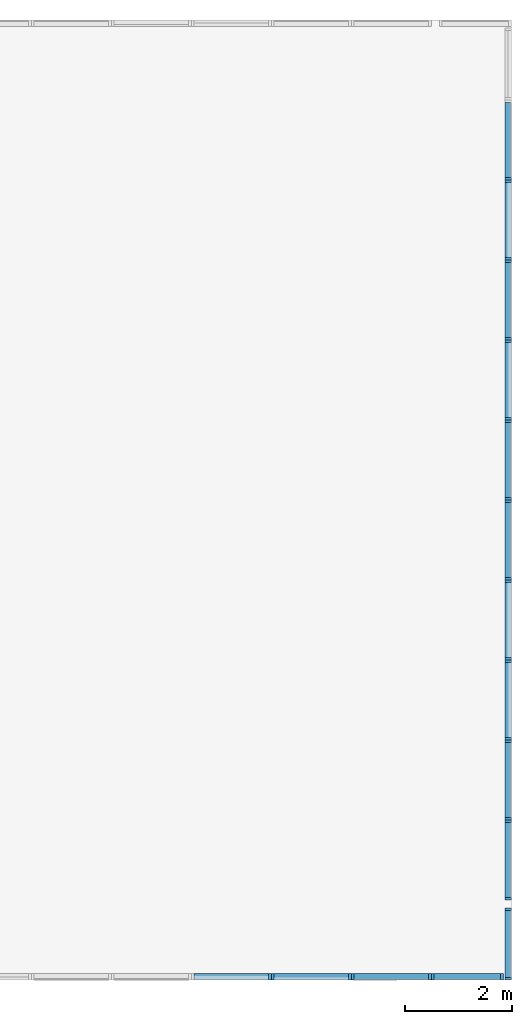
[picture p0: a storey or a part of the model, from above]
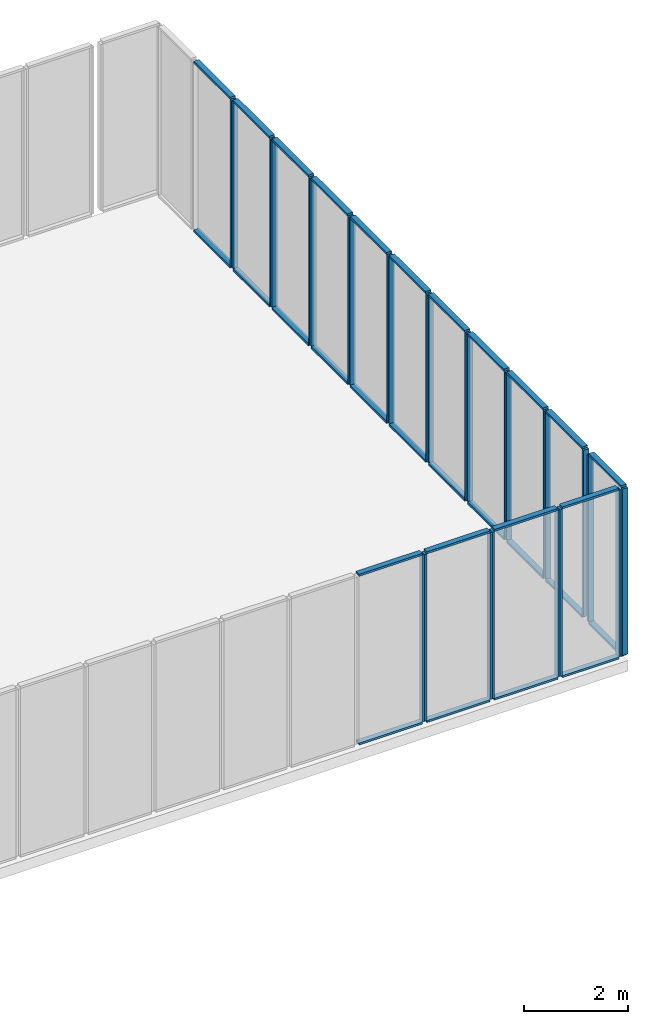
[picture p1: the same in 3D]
Properties of the parts of a building model (IFC4), part 6 of 7

# IfcMember (2304)
Name | In | ElementID | Floor | Elevation | System = Group | Width_mm | Height_mm | Finish | DrawingRef | ParentPanelID
CT-L12-W-007-MR | L12 | CT-L12-W-007-MR | L12 | West | Curtain wall | 50 | 3300 | Blue-grey concept glass | CT-104 | CT-L12-W-007
CT-L12-W-007-FB | L12 | CT-L12-W-007-FB | L12 | West | Curtain wall | 1400 | 50 | Blue-grey concept glass | CT-104 | CT-L12-W-007
CT-L12-W-007-FT | L12 | CT-L12-W-007-FT | L12 | West | Curtain wall | 1400 | 50 | Blue-grey concept glass | CT-104 | CT-L12-W-007
CT-L12-W-008-ML | L12 | CT-L12-W-008-ML | L12 | West | Curtain wall | 50 | 3300 | Blue-grey concept glass | CT-104 | CT-L12-W-008
CT-L12-W-008-MR | L12 | CT-L12-W-008-MR | L12 | West | Curtain wall | 50 | 3300 | Blue-grey concept glass | CT-104 | CT-L12-W-008
CT-L12-W-008-FB | L12 | CT-L12-W-008-FB | L12 | West | Curtain wall | 1250 | 50 | Blue-grey concept glass | CT-104 | CT-L12-W-008
CT-L12-W-008-FT | L12 | CT-L12-W-008-FT | L12 | West | Curtain wall | 1250 | 50 | Blue-grey concept glass | CT-104 | CT-L12-W-008

# IfcMember: Solar shading (57)
PredefinedType: USERDEFINED; Material: Aluminium; Group: Solar shading
ConX_Element - SyntheticData: yes; System: Solar shading; TypeCode: FIN1; Width_mm: 75; Height_mm: 3300; Thickness_mm: 650; Finish: Blue-grey concept glass; DrawingRevision: A
Name | In | ElementID | Floor | Elevation | DrawingRef | ParentPanelID
CT-L04-S-003-FIN | L04 | CT-L04-S-003-FIN | L04 | South | CT-101 | CT-L04-S-003
CT-L04-S-006-FIN | L04 | CT-L04-S-006-FIN | L04 | South | CT-101 | CT-L04-S-006
CT-L04-S-009-FIN | L04 | CT-L04-S-009-FIN | L04 | South | CT-101 | CT-L04-S-009
CT-L04-S-012-FIN | L04 | CT-L04-S-012-FIN | L04 | South | CT-101 | CT-L04-S-012
CT-L04-W-003-FIN | L04 | CT-L04-W-003-FIN | L04 | West | CT-104 | CT-L04-W-003
CT-L04-W-006-FIN | L04 | CT-L04-W-006-FIN | L04 | West | CT-104 | CT-L04-W-006
CT-L04-W-009-FIN | L04 | CT-L04-W-009-FIN | L04 | West | CT-104 | CT-L04-W-009
CT-L05-S-003-FIN | L05 | CT-L05-S-003-FIN | L05 | South | CT-101 | CT-L05-S-003
CT-L05-S-006-FIN | L05 | CT-L05-S-006-FIN | L05 | South | CT-101 | CT-L05-S-006
CT-L05-S-009-FIN | L05 | CT-L05-S-009-FIN | L05 | South | CT-101 | CT-L05-S-009
CT-L05-S-012-FIN | L05 | CT-L05-S-012-FIN | L05 | South | CT-101 | CT-L05-S-012
CT-L05-W-003-FIN | L05 | CT-L05-W-003-FIN | L05 | West | CT-104 | CT-L05-W-003
CT-L05-W-006-FIN | L05 | CT-L05-W-006-FIN | L05 | West | CT-104 | CT-L05-W-006
CT-L05-W-009-FIN | L05 | CT-L05-W-009-FIN | L05 | West | CT-104 | CT-L05-W-009
CT-L06-S-003-FIN | L06 | CT-L06-S-003-FIN | L06 | South | CT-101 | CT-L06-S-003
CT-L06-S-006-FIN | L06 | CT-L06-S-006-FIN | L06 | South | CT-101 | CT-L06-S-006
CT-L06-S-009-FIN | L06 | CT-L06-S-009-FIN | L06 | South | CT-101 | CT-L06-S-009
CT-L06-S-012-FIN | L06 | CT-L06-S-012-FIN | L06 | South | CT-101 | CT-L06-S-012
CT-L06-W-003-FIN | L06 | CT-L06-W-003-FIN | L06 | West | CT-104 | CT-L06-W-003
CT-L06-W-006-FIN | L06 | CT-L06-W-006-FIN | L06 | West | CT-104 | CT-L06-W-006
CT-L06-W-009-FIN | L06 | CT-L06-W-009-FIN | L06 | West | CT-104 | CT-L06-W-009
CT-L07-S-003-FIN | L07 | CT-L07-S-003-FIN | L07 | South | CT-101 | CT-L07-S-003
CT-L07-S-006-FIN | L07 | CT-L07-S-006-FIN | L07 | South | CT-101 | CT-L07-S-006
CT-L07-S-009-FIN | L07 | CT-L07-S-009-FIN | L07 | South | CT-101 | CT-L07-S-009
CT-L07-S-012-FIN | L07 | CT-L07-S-012-FIN | L07 | South | CT-101 | CT-L07-S-012
CT-L07-W-003-FIN | L07 | CT-L07-W-003-FIN | L07 | West | CT-104 | CT-L07-W-003
CT-L07-W-006-FIN | L07 | CT-L07-W-006-FIN | L07 | West | CT-104 | CT-L07-W-006
CT-L07-W-009-FIN | L07 | CT-L07-W-009-FIN | L07 | West | CT-104 | CT-L07-W-009
CT-L08-S-003-FIN | L08 | CT-L08-S-003-FIN | L08 | South | CT-101 | CT-L08-S-003
CT-L08-S-006-FIN | L08 | CT-L08-S-006-FIN | L08 | South | CT-101 | CT-L08-S-006
CT-L08-S-009-FIN | L08 | CT-L08-S-009-FIN | L08 | South | CT-101 | CT-L08-S-009
CT-L08-S-012-FIN | L08 | CT-L08-S-012-FIN | L08 | South | CT-101 | CT-L08-S-012
CT-L08-W-003-FIN | L08 | CT-L08-W-003-FIN | L08 | West | CT-104 | CT-L08-W-003
CT-L08-W-006-FIN | L08 | CT-L08-W-006-FIN | L08 | West | CT-104 | CT-L08-W-006
CT-L08-W-009-FIN | L08 | CT-L08-W-009-FIN | L08 | West | CT-104 | CT-L08-W-009
CT-L09-S-003-FIN | L09 | CT-L09-S-003-FIN | L09 | South | CT-101 | CT-L09-S-003
CT-L09-S-006-FIN | L09 | CT-L09-S-006-FIN | L09 | South | CT-101 | CT-L09-S-006
CT-L09-S-009-FIN | L09 | CT-L09-S-009-FIN | L09 | South | CT-101 | CT-L09-S-009
CT-L09-S-012-FIN | L09 | CT-L09-S-012-FIN | L09 | South | CT-101 | CT-L09-S-012
CT-L09-W-003-FIN | L09 | CT-L09-W-003-FIN | L09 | West | CT-104 | CT-L09-W-003
CT-L09-W-006-FIN | L09 | CT-L09-W-006-FIN | L09 | West | CT-104 | CT-L09-W-006
CT-L09-W-009-FIN | L09 | CT-L09-W-009-FIN | L09 | West | CT-104 | CT-L09-W-009
CT-L10-S-003-FIN | L10 | CT-L10-S-003-FIN | L10 | South | CT-101 | CT-L10-S-003
CT-L10-S-006-FIN | L10 | CT-L10-S-006-FIN | L10 | South | CT-101 | CT-L10-S-006
CT-L10-S-009-FIN | L10 | CT-L10-S-009-FIN | L10 | South | CT-101 | CT-L10-S-009
CT-L10-W-003-FIN | L10 | CT-L10-W-003-FIN | L10 | West | CT-104 | CT-L10-W-003
CT-L10-W-006-FIN | L10 | CT-L10-W-006-FIN | L10 | West | CT-104 | CT-L10-W-006
CT-L11-S-003-FIN | L11 | CT-L11-S-003-FIN | L11 | South | CT-101 | CT-L11-S-003
CT-L11-S-006-FIN | L11 | CT-L11-S-006-FIN | L11 | South | CT-101 | CT-L11-S-006
CT-L11-S-009-FIN | L11 | CT-L11-S-009-FIN | L11 | South | CT-101 | CT-L11-S-009
CT-L11-W-003-FIN | L11 | CT-L11-W-003-FIN | L11 | West | CT-104 | CT-L11-W-003
CT-L11-W-006-FIN | L11 | CT-L11-W-006-FIN | L11 | West | CT-104 | CT-L11-W-006
CT-L12-S-003-FIN | L12 | CT-L12-S-003-FIN | L12 | South | CT-101 | CT-L12-S-003
CT-L12-S-006-FIN | L12 | CT-L12-S-006-FIN | L12 | South | CT-101 | CT-L12-S-006
CT-L12-S-009-FIN | L12 | CT-L12-S-009-FIN | L12 | South | CT-101 | CT-L12-S-009
CT-L12-W-003-FIN | L12 | CT-L12-W-003-FIN | L12 | West | CT-104 | CT-L12-W-003
CT-L12-W-006-FIN | L12 | CT-L12-W-006-FIN | L12 | West | CT-104 | CT-L12-W-006

# IfcPlate (576)
ConX_Element - SyntheticData: yes; DrawingRevision: A
Name | In | PredefinedType | Material | ElementID | Floor | Elevation | System = Group | TypeCode | Width_mm | Height_mm | Thickness_mm | Finish | DrawingRef
CT-L01-S-001 | L01 | CURTAIN_PANEL | Glass | CT-L01-S-001 | L01 | South | Curtain wall | GL1 | 1250 | 3900 | 28 | Blue-grey concept glass | CT-101
CT-L01-S-002 | L01 | CURTAIN_PANEL | Glass | CT-L01-S-002 | L01 | South | Curtain wall | GL1 | 1400 | 3900 | 28 | Blue-grey concept glass | CT-101
CT-L01-S-003 | L01 | CURTAIN_PANEL | Glass | CT-L01-S-003 | L01 | South | Curtain wall | GL1 | 1400 | 3900 | 28 | Blue-grey concept glass | CT-101
CT-L01-S-004 | L01 | SHEET | Stone | CT-L01-S-004 | L01 | South | Stone cladding | ST1 | 1400 | 3900 | 60 | Warm beige stone | CT-101
CT-L01-S-005 | L01 | SHEET | Aluminium | CT-L01-S-005 | L01 | South | Metal rainscreen | AL2 | 1400 | 3900 | 80 | Olive powder coat | CT-101
CT-L01-S-006 | L01 | CURTAIN_PANEL | Glass | CT-L01-S-006 | L01 | South | Curtain wall | GL1 | 1400 | 3900 | 28 | Blue-grey concept glass | CT-101
CT-L01-S-007 | L01 | CURTAIN_PANEL | Glass | CT-L01-S-007 | L01 | South | Curtain wall | GL1 | 1400 | 3900 | 28 | Blue-grey concept glass | CT-101
CT-L01-S-008 | L01 | SHEET | Stone | CT-L01-S-008 | L01 | South | Stone cladding | ST1 | 1400 | 3900 | 60 | Warm beige stone | CT-101
CT-L01-S-009 | L01 | CURTAIN_PANEL | Glass | CT-L01-S-009 | L01 | South | Curtain wall | GL1 | 1400 | 3900 | 28 | Blue-grey concept glass | CT-101
CT-L01-S-010 | L01 | SHEET | Aluminium | CT-L01-S-010 | L01 | South | Metal rainscreen | AL2 | 1400 | 3900 | 80 | Olive powder coat | CT-101
CT-L01-S-011 | L01 | CURTAIN_PANEL | Glass | CT-L01-S-011 | L01 | South | Curtain wall | GL1 | 1400 | 3900 | 28 | Blue-grey concept glass | CT-101
CT-L01-S-012 | L01 | SHEET | Stone | CT-L01-S-012 | L01 | South | Stone cladding | ST1 | 1400 | 3900 | 60 | Warm beige stone | CT-101
CT-L01-S-013 | L01 | CURTAIN_PANEL | Glass | CT-L01-S-013 | L01 | South | Curtain wall | GL1 | 1400 | 3900 | 28 | Blue-grey concept glass | CT-101
CT-L01-S-014 | L01 | CURTAIN_PANEL | Glass | CT-L01-S-014 | L01 | South | Curtain wall | GL1 | 1400 | 3900 | 28 | Blue-grey concept glass | CT-101
CT-L01-S-015 | L01 | SHEET | Aluminium | CT-L01-S-015 | L01 | South | Metal rainscreen | AL2 | 1400 | 3900 | 80 | Olive powder coat | CT-101
CT-L01-S-016 | L01 | SHEET | Stone | CT-L01-S-016 | L01 | South | Stone cladding | ST1 | 1400 | 3900 | 60 | Warm beige stone | CT-101
CT-L01-S-017 | L01 | CURTAIN_PANEL | Glass | CT-L01-S-017 | L01 | South | Curtain wall | GL1 | 1400 | 3900 | 28 | Blue-grey concept glass | CT-101
CT-L01-S-018 | L01 | CURTAIN_PANEL | Glass | CT-L01-S-018 | L01 | South | Curtain wall | GL1 | 1250 | 3900 | 28 | Blue-grey concept glass | CT-101
CT-L01-E-001 | L01 | CURTAIN_PANEL | Glass | CT-L01-E-001 | L01 | East | Curtain wall | GL1 | 1250 | 3900 | 28 | Blue-grey concept glass | CT-102
CT-L01-E-002 | L01 | CURTAIN_PANEL | Glass | CT-L01-E-002 | L01 | East | Curtain wall | GL1 | 1400 | 3900 | 28 | Blue-grey concept glass | CT-102
CT-L01-E-003 | L01 | CURTAIN_PANEL | Glass | CT-L01-E-003 | L01 | East | Curtain wall | GL1 | 1400 | 3900 | 28 | Blue-grey concept glass | CT-102
CT-L01-E-004 | L01 | SHEET | Stone | CT-L01-E-004 | L01 | East | Stone cladding | ST1 | 1400 | 3900 | 60 | Warm beige stone | CT-102
CT-L01-E-005 | L01 | SHEET | Aluminium | CT-L01-E-005 | L01 | East | Metal rainscreen | AL2 | 1400 | 3900 | 80 | Olive powder coat | CT-102
CT-L01-E-006 | L01 | CURTAIN_PANEL | Glass | CT-L01-E-006 | L01 | East | Curtain wall | GL1 | 1400 | 3900 | 28 | Blue-grey concept glass | CT-102
CT-L01-E-007 | L01 | CURTAIN_PANEL | Glass | CT-L01-E-007 | L01 | East | Curtain wall | GL1 | 1400 | 3900 | 28 | Blue-grey concept glass | CT-102
CT-L01-E-008 | L01 | SHEET | Stone | CT-L01-E-008 | L01 | East | Stone cladding | ST1 | 1400 | 3900 | 60 | Warm beige stone | CT-102
CT-L01-E-009 | L01 | CURTAIN_PANEL | Glass | CT-L01-E-009 | L01 | East | Curtain wall | GL1 | 1400 | 3900 | 28 | Blue-grey concept glass | CT-102
CT-L01-E-010 | L01 | SHEET | Aluminium | CT-L01-E-010 | L01 | East | Metal rainscreen | AL2 | 1400 | 3900 | 80 | Olive powder coat | CT-102
CT-L01-E-011 | L01 | CURTAIN_PANEL | Glass | CT-L01-E-011 | L01 | East | Curtain wall | GL1 | 1400 | 3900 | 28 | Blue-grey concept glass | CT-102
CT-L01-E-012 | L01 | SHEET | Stone | CT-L01-E-012 | L01 | East | Stone cladding | ST1 | 1250 | 3900 | 60 | Warm beige stone | CT-102
CT-L01-N-001 | L01 | CURTAIN_PANEL | Glass | CT-L01-N-001 | L01 | North | Curtain wall | GL1 | 1250 | 3900 | 28 | Blue-grey concept glass | CT-103
CT-L01-N-002 | L01 | CURTAIN_PANEL | Glass | CT-L01-N-002 | L01 | North | Curtain wall | GL1 | 1400 | 3900 | 28 | Blue-grey concept glass | CT-103
CT-L01-N-003 | L01 | CURTAIN_PANEL | Glass | CT-L01-N-003 | L01 | North | Curtain wall | GL1 | 1400 | 3900 | 28 | Blue-grey concept glass | CT-103
CT-L01-N-004 | L01 | SHEET | Stone | CT-L01-N-004 | L01 | North | Stone cladding | ST1 | 1400 | 3900 | 60 | Warm beige stone | CT-103
CT-L01-N-005 | L01 | SHEET | Aluminium | CT-L01-N-005 | L01 | North | Metal rainscreen | AL2 | 1400 | 3900 | 80 | Olive powder coat | CT-103
CT-L01-N-006 | L01 | CURTAIN_PANEL | Glass | CT-L01-N-006 | L01 | North | Curtain wall | GL1 | 1400 | 3900 | 28 | Blue-grey concept glass | CT-103
CT-L01-N-007 | L01 | CURTAIN_PANEL | Glass | CT-L01-N-007 | L01 | North | Curtain wall | GL1 | 1400 | 3900 | 28 | Blue-grey concept glass | CT-103
CT-L01-N-008 | L01 | SHEET | Stone | CT-L01-N-008 | L01 | North | Stone cladding | ST1 | 1400 | 3900 | 60 | Warm beige stone | CT-103
CT-L01-N-009 | L01 | CURTAIN_PANEL | Glass | CT-L01-N-009 | L01 | North | Curtain wall | GL1 | 1400 | 3900 | 28 | Blue-grey concept glass | CT-103
CT-L01-N-010 | L01 | SHEET | Aluminium | CT-L01-N-010 | L01 | North | Metal rainscreen | AL2 | 1400 | 3900 | 80 | Olive powder coat | CT-103
CT-L01-N-011 | L01 | CURTAIN_PANEL | Glass | CT-L01-N-011 | L01 | North | Curtain wall | GL1 | 1400 | 3900 | 28 | Blue-grey concept glass | CT-103
CT-L01-N-012 | L01 | SHEET | Stone | CT-L01-N-012 | L01 | North | Stone cladding | ST1 | 1400 | 3900 | 60 | Warm beige stone | CT-103
CT-L01-N-013 | L01 | CURTAIN_PANEL | Glass | CT-L01-N-013 | L01 | North | Curtain wall | GL1 | 1400 | 3900 | 28 | Blue-grey concept glass | CT-103
CT-L01-N-014 | L01 | CURTAIN_PANEL | Glass | CT-L01-N-014 | L01 | North | Curtain wall | GL1 | 1400 | 3900 | 28 | Blue-grey concept glass | CT-103
CT-L01-N-015 | L01 | SHEET | Aluminium | CT-L01-N-015 | L01 | North | Metal rainscreen | AL2 | 1400 | 3900 | 80 | Olive powder coat | CT-103
CT-L01-N-016 | L01 | SHEET | Stone | CT-L01-N-016 | L01 | North | Stone cladding | ST1 | 1400 | 3900 | 60 | Warm beige stone | CT-103
CT-L01-N-017 | L01 | CURTAIN_PANEL | Glass | CT-L01-N-017 | L01 | North | Curtain wall | GL1 | 1400 | 3900 | 28 | Blue-grey concept glass | CT-103
CT-L01-N-018 | L01 | CURTAIN_PANEL | Glass | CT-L01-N-018 | L01 | North | Curtain wall | GL1 | 1250 | 3900 | 28 | Blue-grey concept glass | CT-103
CT-L01-W-001 | L01 | CURTAIN_PANEL | Glass | CT-L01-W-001 | L01 | West | Curtain wall | GL1 | 1250 | 3900 | 28 | Blue-grey concept glass | CT-104
CT-L01-W-002 | L01 | CURTAIN_PANEL | Glass | CT-L01-W-002 | L01 | West | Curtain wall | GL1 | 1400 | 3900 | 28 | Blue-grey concept glass | CT-104
CT-L01-W-003 | L01 | CURTAIN_PANEL | Glass | CT-L01-W-003 | L01 | West | Curtain wall | GL1 | 1400 | 3900 | 28 | Blue-grey concept glass | CT-104
CT-L01-W-004 | L01 | SHEET | Stone | CT-L01-W-004 | L01 | West | Stone cladding | ST1 | 1400 | 3900 | 60 | Warm beige stone | CT-104
CT-L01-W-005 | L01 | SHEET | Aluminium | CT-L01-W-005 | L01 | West | Metal rainscreen | AL2 | 1400 | 3900 | 80 | Olive powder coat | CT-104
CT-L01-W-006 | L01 | CURTAIN_PANEL | Glass | CT-L01-W-006 | L01 | West | Curtain wall | GL1 | 1400 | 3900 | 28 | Blue-grey concept glass | CT-104
CT-L01-W-007 | L01 | CURTAIN_PANEL | Glass | CT-L01-W-007 | L01 | West | Curtain wall | GL1 | 1400 | 3900 | 28 | Blue-grey concept glass | CT-104
CT-L01-W-008 | L01 | SHEET | Stone | CT-L01-W-008 | L01 | West | Stone cladding | ST1 | 1400 | 3900 | 60 | Warm beige stone | CT-104
CT-L01-W-009 | L01 | CURTAIN_PANEL | Glass | CT-L01-W-009 | L01 | West | Curtain wall | GL1 | 1400 | 3900 | 28 | Blue-grey concept glass | CT-104
CT-L01-W-010 | L01 | SHEET | Aluminium | CT-L01-W-010 | L01 | West | Metal rainscreen | AL2 | 1400 | 3900 | 80 | Olive powder coat | CT-104
CT-L01-W-011 | L01 | CURTAIN_PANEL | Glass | CT-L01-W-011 | L01 | West | Curtain wall | GL1 | 1400 | 3900 | 28 | Blue-grey concept glass | CT-104
CT-L01-W-012 | L01 | SHEET | Stone | CT-L01-W-012 | L01 | West | Stone cladding | ST1 | 1250 | 3900 | 60 | Warm beige stone | CT-104
CT-L02-S-001 | L02 | CURTAIN_PANEL | Glass | CT-L02-S-001 | L02 | South | Curtain wall | GL1 | 1250 | 3900 | 28 | Blue-grey concept glass | CT-101
CT-L02-S-002 | L02 | CURTAIN_PANEL | Glass | CT-L02-S-002 | L02 | South | Curtain wall | GL1 | 1400 | 3900 | 28 | Blue-grey concept glass | CT-101
CT-L02-S-003 | L02 | CURTAIN_PANEL | Glass | CT-L02-S-003 | L02 | South | Curtain wall | GL1 | 1400 | 3900 | 28 | Blue-grey concept glass | CT-101
CT-L02-S-004 | L02 | SHEET | Stone | CT-L02-S-004 | L02 | South | Stone cladding | ST1 | 1400 | 3900 | 60 | Warm beige stone | CT-101
CT-L02-S-005 | L02 | SHEET | Aluminium | CT-L02-S-005 | L02 | South | Metal rainscreen | AL2 | 1400 | 3900 | 80 | Olive powder coat | CT-101
CT-L02-S-006 | L02 | CURTAIN_PANEL | Glass | CT-L02-S-006 | L02 | South | Curtain wall | GL1 | 1400 | 3900 | 28 | Blue-grey concept glass | CT-101
CT-L02-S-007 | L02 | CURTAIN_PANEL | Glass | CT-L02-S-007 | L02 | South | Curtain wall | GL1 | 1400 | 3900 | 28 | Blue-grey concept glass | CT-101
CT-L02-S-008 | L02 | SHEET | Stone | CT-L02-S-008 | L02 | South | Stone cladding | ST1 | 1400 | 3900 | 60 | Warm beige stone | CT-101
CT-L02-S-009 | L02 | CURTAIN_PANEL | Glass | CT-L02-S-009 | L02 | South | Curtain wall | GL1 | 1400 | 3900 | 28 | Blue-grey concept glass | CT-101
CT-L02-S-010 | L02 | SHEET | Aluminium | CT-L02-S-010 | L02 | South | Metal rainscreen | AL2 | 1400 | 3900 | 80 | Olive powder coat | CT-101
CT-L02-S-011 | L02 | CURTAIN_PANEL | Glass | CT-L02-S-011 | L02 | South | Curtain wall | GL1 | 1400 | 3900 | 28 | Blue-grey concept glass | CT-101
CT-L02-S-012 | L02 | SHEET | Stone | CT-L02-S-012 | L02 | South | Stone cladding | ST1 | 1400 | 3900 | 60 | Warm beige stone | CT-101
CT-L02-S-013 | L02 | CURTAIN_PANEL | Glass | CT-L02-S-013 | L02 | South | Curtain wall | GL1 | 1400 | 3900 | 28 | Blue-grey concept glass | CT-101
CT-L02-S-014 | L02 | CURTAIN_PANEL | Glass | CT-L02-S-014 | L02 | South | Curtain wall | GL1 | 1400 | 3900 | 28 | Blue-grey concept glass | CT-101
CT-L02-S-015 | L02 | SHEET | Aluminium | CT-L02-S-015 | L02 | South | Metal rainscreen | AL2 | 1400 | 3900 | 80 | Olive powder coat | CT-101
CT-L02-S-016 | L02 | SHEET | Stone | CT-L02-S-016 | L02 | South | Stone cladding | ST1 | 1400 | 3900 | 60 | Warm beige stone | CT-101
CT-L02-S-017 | L02 | CURTAIN_PANEL | Glass | CT-L02-S-017 | L02 | South | Curtain wall | GL1 | 1400 | 3900 | 28 | Blue-grey concept glass | CT-101
CT-L02-S-018 | L02 | CURTAIN_PANEL | Glass | CT-L02-S-018 | L02 | South | Curtain wall | GL1 | 1250 | 3900 | 28 | Blue-grey concept glass | CT-101
CT-L02-E-001 | L02 | CURTAIN_PANEL | Glass | CT-L02-E-001 | L02 | East | Curtain wall | GL1 | 1250 | 3900 | 28 | Blue-grey concept glass | CT-102
CT-L02-E-002 | L02 | CURTAIN_PANEL | Glass | CT-L02-E-002 | L02 | East | Curtain wall | GL1 | 1400 | 3900 | 28 | Blue-grey concept glass | CT-102
CT-L02-E-003 | L02 | CURTAIN_PANEL | Glass | CT-L02-E-003 | L02 | East | Curtain wall | GL1 | 1400 | 3900 | 28 | Blue-grey concept glass | CT-102
CT-L02-E-004 | L02 | SHEET | Stone | CT-L02-E-004 | L02 | East | Stone cladding | ST1 | 1400 | 3900 | 60 | Warm beige stone | CT-102
CT-L02-E-005 | L02 | SHEET | Aluminium | CT-L02-E-005 | L02 | East | Metal rainscreen | AL2 | 1400 | 3900 | 80 | Olive powder coat | CT-102
CT-L02-E-006 | L02 | CURTAIN_PANEL | Glass | CT-L02-E-006 | L02 | East | Curtain wall | GL1 | 1400 | 3900 | 28 | Blue-grey concept glass | CT-102
CT-L02-E-007 | L02 | CURTAIN_PANEL | Glass | CT-L02-E-007 | L02 | East | Curtain wall | GL1 | 1400 | 3900 | 28 | Blue-grey concept glass | CT-102
CT-L02-E-008 | L02 | SHEET | Stone | CT-L02-E-008 | L02 | East | Stone cladding | ST1 | 1400 | 3900 | 60 | Warm beige stone | CT-102
CT-L02-E-009 | L02 | CURTAIN_PANEL | Glass | CT-L02-E-009 | L02 | East | Curtain wall | GL1 | 1400 | 3900 | 28 | Blue-grey concept glass | CT-102
CT-L02-E-010 | L02 | SHEET | Aluminium | CT-L02-E-010 | L02 | East | Metal rainscreen | AL2 | 1400 | 3900 | 80 | Olive powder coat | CT-102
CT-L02-E-011 | L02 | CURTAIN_PANEL | Glass | CT-L02-E-011 | L02 | East | Curtain wall | GL1 | 1400 | 3900 | 28 | Blue-grey concept glass | CT-102
CT-L02-E-012 | L02 | SHEET | Stone | CT-L02-E-012 | L02 | East | Stone cladding | ST1 | 1250 | 3900 | 60 | Warm beige stone | CT-102
CT-L02-N-001 | L02 | CURTAIN_PANEL | Glass | CT-L02-N-001 | L02 | North | Curtain wall | GL1 | 1250 | 3900 | 28 | Blue-grey concept glass | CT-103
CT-L02-N-002 | L02 | CURTAIN_PANEL | Glass | CT-L02-N-002 | L02 | North | Curtain wall | GL1 | 1400 | 3900 | 28 | Blue-grey concept glass | CT-103
CT-L02-N-003 | L02 | CURTAIN_PANEL | Glass | CT-L02-N-003 | L02 | North | Curtain wall | GL1 | 1400 | 3900 | 28 | Blue-grey concept glass | CT-103
CT-L02-N-004 | L02 | SHEET | Stone | CT-L02-N-004 | L02 | North | Stone cladding | ST1 | 1400 | 3900 | 60 | Warm beige stone | CT-103
CT-L02-N-005 | L02 | SHEET | Aluminium | CT-L02-N-005 | L02 | North | Metal rainscreen | AL2 | 1400 | 3900 | 80 | Olive powder coat | CT-103
CT-L02-N-006 | L02 | CURTAIN_PANEL | Glass | CT-L02-N-006 | L02 | North | Curtain wall | GL1 | 1400 | 3900 | 28 | Blue-grey concept glass | CT-103
CT-L02-N-007 | L02 | CURTAIN_PANEL | Glass | CT-L02-N-007 | L02 | North | Curtain wall | GL1 | 1400 | 3900 | 28 | Blue-grey concept glass | CT-103
CT-L02-N-008 | L02 | SHEET | Stone | CT-L02-N-008 | L02 | North | Stone cladding | ST1 | 1400 | 3900 | 60 | Warm beige stone | CT-103
CT-L02-N-009 | L02 | CURTAIN_PANEL | Glass | CT-L02-N-009 | L02 | North | Curtain wall | GL1 | 1400 | 3900 | 28 | Blue-grey concept glass | CT-103
CT-L02-N-010 | L02 | SHEET | Aluminium | CT-L02-N-010 | L02 | North | Metal rainscreen | AL2 | 1400 | 3900 | 80 | Olive powder coat | CT-103
CT-L02-N-011 | L02 | CURTAIN_PANEL | Glass | CT-L02-N-011 | L02 | North | Curtain wall | GL1 | 1400 | 3900 | 28 | Blue-grey concept glass | CT-103
CT-L02-N-012 | L02 | SHEET | Stone | CT-L02-N-012 | L02 | North | Stone cladding | ST1 | 1400 | 3900 | 60 | Warm beige stone | CT-103
CT-L02-N-013 | L02 | CURTAIN_PANEL | Glass | CT-L02-N-013 | L02 | North | Curtain wall | GL1 | 1400 | 3900 | 28 | Blue-grey concept glass | CT-103
CT-L02-N-014 | L02 | CURTAIN_PANEL | Glass | CT-L02-N-014 | L02 | North | Curtain wall | GL1 | 1400 | 3900 | 28 | Blue-grey concept glass | CT-103
CT-L02-N-015 | L02 | SHEET | Aluminium | CT-L02-N-015 | L02 | North | Metal rainscreen | AL2 | 1400 | 3900 | 80 | Olive powder coat | CT-103
CT-L02-N-016 | L02 | SHEET | Stone | CT-L02-N-016 | L02 | North | Stone cladding | ST1 | 1400 | 3900 | 60 | Warm beige stone | CT-103
CT-L02-N-017 | L02 | CURTAIN_PANEL | Glass | CT-L02-N-017 | L02 | North | Curtain wall | GL1 | 1400 | 3900 | 28 | Blue-grey concept glass | CT-103
CT-L02-N-018 | L02 | CURTAIN_PANEL | Glass | CT-L02-N-018 | L02 | North | Curtain wall | GL1 | 1250 | 3900 | 28 | Blue-grey concept glass | CT-103
CT-L02-W-001 | L02 | CURTAIN_PANEL | Glass | CT-L02-W-001 | L02 | West | Curtain wall | GL1 | 1250 | 3900 | 28 | Blue-grey concept glass | CT-104
CT-L02-W-002 | L02 | CURTAIN_PANEL | Glass | CT-L02-W-002 | L02 | West | Curtain wall | GL1 | 1400 | 3900 | 28 | Blue-grey concept glass | CT-104
CT-L02-W-003 | L02 | CURTAIN_PANEL | Glass | CT-L02-W-003 | L02 | West | Curtain wall | GL1 | 1400 | 3900 | 28 | Blue-grey concept glass | CT-104
CT-L02-W-004 | L02 | SHEET | Stone | CT-L02-W-004 | L02 | West | Stone cladding | ST1 | 1400 | 3900 | 60 | Warm beige stone | CT-104
CT-L02-W-005 | L02 | SHEET | Aluminium | CT-L02-W-005 | L02 | West | Metal rainscreen | AL2 | 1400 | 3900 | 80 | Olive powder coat | CT-104
CT-L02-W-006 | L02 | CURTAIN_PANEL | Glass | CT-L02-W-006 | L02 | West | Curtain wall | GL1 | 1400 | 3900 | 28 | Blue-grey concept glass | CT-104
CT-L02-W-007 | L02 | CURTAIN_PANEL | Glass | CT-L02-W-007 | L02 | West | Curtain wall | GL1 | 1400 | 3900 | 28 | Blue-grey concept glass | CT-104
CT-L02-W-008 | L02 | SHEET | Stone | CT-L02-W-008 | L02 | West | Stone cladding | ST1 | 1400 | 3900 | 60 | Warm beige stone | CT-104
CT-L02-W-009 | L02 | CURTAIN_PANEL | Glass | CT-L02-W-009 | L02 | West | Curtain wall | GL1 | 1400 | 3900 | 28 | Blue-grey concept glass | CT-104
CT-L02-W-010 | L02 | SHEET | Aluminium | CT-L02-W-010 | L02 | West | Metal rainscreen | AL2 | 1400 | 3900 | 80 | Olive powder coat | CT-104
CT-L02-W-011 | L02 | CURTAIN_PANEL | Glass | CT-L02-W-011 | L02 | West | Curtain wall | GL1 | 1400 | 3900 | 28 | Blue-grey concept glass | CT-104
CT-L02-W-012 | L02 | SHEET | Stone | CT-L02-W-012 | L02 | West | Stone cladding | ST1 | 1250 | 3900 | 60 | Warm beige stone | CT-104
CT-L03-S-001 | L03 | CURTAIN_PANEL | Glass | CT-L03-S-001 | L03 | South | Curtain wall | GL1 | 1250 | 3900 | 28 | Blue-grey concept glass | CT-101
CT-L03-S-002 | L03 | CURTAIN_PANEL | Glass | CT-L03-S-002 | L03 | South | Curtain wall | GL1 | 1400 | 3900 | 28 | Blue-grey concept glass | CT-101
CT-L03-S-003 | L03 | CURTAIN_PANEL | Glass | CT-L03-S-003 | L03 | South | Curtain wall | GL1 | 1400 | 3900 | 28 | Blue-grey concept glass | CT-101
CT-L03-S-004 | L03 | SHEET | Stone | CT-L03-S-004 | L03 | South | Stone cladding | ST1 | 1400 | 3900 | 60 | Warm beige stone | CT-101
CT-L03-S-005 | L03 | SHEET | Aluminium | CT-L03-S-005 | L03 | South | Metal rainscreen | AL2 | 1400 | 3900 | 80 | Olive powder coat | CT-101
CT-L03-S-006 | L03 | CURTAIN_PANEL | Glass | CT-L03-S-006 | L03 | South | Curtain wall | GL1 | 1400 | 3900 | 28 | Blue-grey concept glass | CT-101
CT-L03-S-007 | L03 | CURTAIN_PANEL | Glass | CT-L03-S-007 | L03 | South | Curtain wall | GL1 | 1400 | 3900 | 28 | Blue-grey concept glass | CT-101
CT-L03-S-008 | L03 | SHEET | Stone | CT-L03-S-008 | L03 | South | Stone cladding | ST1 | 1400 | 3900 | 60 | Warm beige stone | CT-101
CT-L03-S-009 | L03 | CURTAIN_PANEL | Glass | CT-L03-S-009 | L03 | South | Curtain wall | GL1 | 1400 | 3900 | 28 | Blue-grey concept glass | CT-101
CT-L03-S-010 | L03 | SHEET | Aluminium | CT-L03-S-010 | L03 | South | Metal rainscreen | AL2 | 1400 | 3900 | 80 | Olive powder coat | CT-101
CT-L03-S-011 | L03 | CURTAIN_PANEL | Glass | CT-L03-S-011 | L03 | South | Curtain wall | GL1 | 1400 | 3900 | 28 | Blue-grey concept glass | CT-101
CT-L03-S-012 | L03 | SHEET | Stone | CT-L03-S-012 | L03 | South | Stone cladding | ST1 | 1400 | 3900 | 60 | Warm beige stone | CT-101
CT-L03-S-013 | L03 | CURTAIN_PANEL | Glass | CT-L03-S-013 | L03 | South | Curtain wall | GL1 | 1400 | 3900 | 28 | Blue-grey concept glass | CT-101
CT-L03-S-014 | L03 | CURTAIN_PANEL | Glass | CT-L03-S-014 | L03 | South | Curtain wall | GL1 | 1400 | 3900 | 28 | Blue-grey concept glass | CT-101
CT-L03-S-015 | L03 | SHEET | Aluminium | CT-L03-S-015 | L03 | South | Metal rainscreen | AL2 | 1400 | 3900 | 80 | Olive powder coat | CT-101
CT-L03-S-016 | L03 | SHEET | Stone | CT-L03-S-016 | L03 | South | Stone cladding | ST1 | 1400 | 3900 | 60 | Warm beige stone | CT-101
CT-L03-S-017 | L03 | CURTAIN_PANEL | Glass | CT-L03-S-017 | L03 | South | Curtain wall | GL1 | 1400 | 3900 | 28 | Blue-grey concept glass | CT-101
CT-L03-S-018 | L03 | CURTAIN_PANEL | Glass | CT-L03-S-018 | L03 | South | Curtain wall | GL1 | 1250 | 3900 | 28 | Blue-grey concept glass | CT-101
CT-L03-E-001 | L03 | CURTAIN_PANEL | Glass | CT-L03-E-001 | L03 | East | Curtain wall | GL1 | 1250 | 3900 | 28 | Blue-grey concept glass | CT-102
CT-L03-E-002 | L03 | CURTAIN_PANEL | Glass | CT-L03-E-002 | L03 | East | Curtain wall | GL1 | 1400 | 3900 | 28 | Blue-grey concept glass | CT-102
CT-L03-E-003 | L03 | CURTAIN_PANEL | Glass | CT-L03-E-003 | L03 | East | Curtain wall | GL1 | 1400 | 3900 | 28 | Blue-grey concept glass | CT-102
CT-L03-E-004 | L03 | SHEET | Stone | CT-L03-E-004 | L03 | East | Stone cladding | ST1 | 1400 | 3900 | 60 | Warm beige stone | CT-102
CT-L03-E-005 | L03 | SHEET | Aluminium | CT-L03-E-005 | L03 | East | Metal rainscreen | AL2 | 1400 | 3900 | 80 | Olive powder coat | CT-102
CT-L03-E-006 | L03 | CURTAIN_PANEL | Glass | CT-L03-E-006 | L03 | East | Curtain wall | GL1 | 1400 | 3900 | 28 | Blue-grey concept glass | CT-102
CT-L03-E-007 | L03 | CURTAIN_PANEL | Glass | CT-L03-E-007 | L03 | East | Curtain wall | GL1 | 1400 | 3900 | 28 | Blue-grey concept glass | CT-102
CT-L03-E-008 | L03 | SHEET | Stone | CT-L03-E-008 | L03 | East | Stone cladding | ST1 | 1400 | 3900 | 60 | Warm beige stone | CT-102
CT-L03-E-009 | L03 | CURTAIN_PANEL | Glass | CT-L03-E-009 | L03 | East | Curtain wall | GL1 | 1400 | 3900 | 28 | Blue-grey concept glass | CT-102
CT-L03-E-010 | L03 | SHEET | Aluminium | CT-L03-E-010 | L03 | East | Metal rainscreen | AL2 | 1400 | 3900 | 80 | Olive powder coat | CT-102
CT-L03-E-011 | L03 | CURTAIN_PANEL | Glass | CT-L03-E-011 | L03 | East | Curtain wall | GL1 | 1400 | 3900 | 28 | Blue-grey concept glass | CT-102
CT-L03-E-012 | L03 | SHEET | Stone | CT-L03-E-012 | L03 | East | Stone cladding | ST1 | 1250 | 3900 | 60 | Warm beige stone | CT-102
CT-L03-N-001 | L03 | CURTAIN_PANEL | Glass | CT-L03-N-001 | L03 | North | Curtain wall | GL1 | 1250 | 3900 | 28 | Blue-grey concept glass | CT-103
CT-L03-N-002 | L03 | CURTAIN_PANEL | Glass | CT-L03-N-002 | L03 | North | Curtain wall | GL1 | 1400 | 3900 | 28 | Blue-grey concept glass | CT-103
CT-L03-N-003 | L03 | CURTAIN_PANEL | Glass | CT-L03-N-003 | L03 | North | Curtain wall | GL1 | 1400 | 3900 | 28 | Blue-grey concept glass | CT-103
CT-L03-N-004 | L03 | SHEET | Stone | CT-L03-N-004 | L03 | North | Stone cladding | ST1 | 1400 | 3900 | 60 | Warm beige stone | CT-103
CT-L03-N-005 | L03 | SHEET | Aluminium | CT-L03-N-005 | L03 | North | Metal rainscreen | AL2 | 1400 | 3900 | 80 | Olive powder coat | CT-103
CT-L03-N-006 | L03 | CURTAIN_PANEL | Glass | CT-L03-N-006 | L03 | North | Curtain wall | GL1 | 1400 | 3900 | 28 | Blue-grey concept glass | CT-103
CT-L03-N-007 | L03 | CURTAIN_PANEL | Glass | CT-L03-N-007 | L03 | North | Curtain wall | GL1 | 1400 | 3900 | 28 | Blue-grey concept glass | CT-103
CT-L03-N-008 | L03 | SHEET | Stone | CT-L03-N-008 | L03 | North | Stone cladding | ST1 | 1400 | 3900 | 60 | Warm beige stone | CT-103
CT-L03-N-009 | L03 | CURTAIN_PANEL | Glass | CT-L03-N-009 | L03 | North | Curtain wall | GL1 | 1400 | 3900 | 28 | Blue-grey concept glass | CT-103
CT-L03-N-010 | L03 | SHEET | Aluminium | CT-L03-N-010 | L03 | North | Metal rainscreen | AL2 | 1400 | 3900 | 80 | Olive powder coat | CT-103
CT-L03-N-011 | L03 | CURTAIN_PANEL | Glass | CT-L03-N-011 | L03 | North | Curtain wall | GL1 | 1400 | 3900 | 28 | Blue-grey concept glass | CT-103
CT-L03-N-012 | L03 | SHEET | Stone | CT-L03-N-012 | L03 | North | Stone cladding | ST1 | 1400 | 3900 | 60 | Warm beige stone | CT-103
CT-L03-N-013 | L03 | CURTAIN_PANEL | Glass | CT-L03-N-013 | L03 | North | Curtain wall | GL1 | 1400 | 3900 | 28 | Blue-grey concept glass | CT-103
CT-L03-N-014 | L03 | CURTAIN_PANEL | Glass | CT-L03-N-014 | L03 | North | Curtain wall | GL1 | 1400 | 3900 | 28 | Blue-grey concept glass | CT-103
CT-L03-N-015 | L03 | SHEET | Aluminium | CT-L03-N-015 | L03 | North | Metal rainscreen | AL2 | 1400 | 3900 | 80 | Olive powder coat | CT-103
CT-L03-N-016 | L03 | SHEET | Stone | CT-L03-N-016 | L03 | North | Stone cladding | ST1 | 1400 | 3900 | 60 | Warm beige stone | CT-103
CT-L03-N-017 | L03 | CURTAIN_PANEL | Glass | CT-L03-N-017 | L03 | North | Curtain wall | GL1 | 1400 | 3900 | 28 | Blue-grey concept glass | CT-103
CT-L03-N-018 | L03 | CURTAIN_PANEL | Glass | CT-L03-N-018 | L03 | North | Curtain wall | GL1 | 1250 | 3900 | 28 | Blue-grey concept glass | CT-103
CT-L03-W-001 | L03 | CURTAIN_PANEL | Glass | CT-L03-W-001 | L03 | West | Curtain wall | GL1 | 1250 | 3900 | 28 | Blue-grey concept glass | CT-104
CT-L03-W-002 | L03 | CURTAIN_PANEL | Glass | CT-L03-W-002 | L03 | West | Curtain wall | GL1 | 1400 | 3900 | 28 | Blue-grey concept glass | CT-104
CT-L03-W-003 | L03 | CURTAIN_PANEL | Glass | CT-L03-W-003 | L03 | West | Curtain wall | GL1 | 1400 | 3900 | 28 | Blue-grey concept glass | CT-104
CT-L03-W-004 | L03 | SHEET | Stone | CT-L03-W-004 | L03 | West | Stone cladding | ST1 | 1400 | 3900 | 60 | Warm beige stone | CT-104
CT-L03-W-005 | L03 | SHEET | Aluminium | CT-L03-W-005 | L03 | West | Metal rainscreen | AL2 | 1400 | 3900 | 80 | Olive powder coat | CT-104
CT-L03-W-006 | L03 | CURTAIN_PANEL | Glass | CT-L03-W-006 | L03 | West | Curtain wall | GL1 | 1400 | 3900 | 28 | Blue-grey concept glass | CT-104
CT-L03-W-007 | L03 | CURTAIN_PANEL | Glass | CT-L03-W-007 | L03 | West | Curtain wall | GL1 | 1400 | 3900 | 28 | Blue-grey concept glass | CT-104
CT-L03-W-008 | L03 | SHEET | Stone | CT-L03-W-008 | L03 | West | Stone cladding | ST1 | 1400 | 3900 | 60 | Warm beige stone | CT-104
CT-L03-W-009 | L03 | CURTAIN_PANEL | Glass | CT-L03-W-009 | L03 | West | Curtain wall | GL1 | 1400 | 3900 | 28 | Blue-grey concept glass | CT-104
CT-L03-W-010 | L03 | SHEET | Aluminium | CT-L03-W-010 | L03 | West | Metal rainscreen | AL2 | 1400 | 3900 | 80 | Olive powder coat | CT-104
CT-L03-W-011 | L03 | CURTAIN_PANEL | Glass | CT-L03-W-011 | L03 | West | Curtain wall | GL1 | 1400 | 3900 | 28 | Blue-grey concept glass | CT-104
CT-L03-W-012 | L03 | SHEET | Stone | CT-L03-W-012 | L03 | West | Stone cladding | ST1 | 1250 | 3900 | 60 | Warm beige stone | CT-104
CT-L04-S-001 | L04 | CURTAIN_PANEL | Glass | CT-L04-S-001 | L04 | South | Curtain wall | GL1 | 1250 | 3300 | 28 | Blue-grey concept glass | CT-101
CT-L04-S-002 | L04 | CURTAIN_PANEL | Glass | CT-L04-S-002 | L04 | South | Curtain wall | GL1 | 1400 | 3300 | 28 | Blue-grey concept glass | CT-101
CT-L04-S-003 | L04 | CURTAIN_PANEL | Glass | CT-L04-S-003 | L04 | South | Curtain wall | GL1 | 1400 | 3300 | 28 | Blue-grey concept glass | CT-101
CT-L04-S-004 | L04 | CURTAIN_PANEL | Glass | CT-L04-S-004 | L04 | South | Curtain wall | GL1 | 1400 | 3300 | 28 | Blue-grey concept glass | CT-101
CT-L04-S-005 | L04 | SHEET | Aluminium | CT-L04-S-005 | L04 | South | Metal rainscreen | AL2 | 1400 | 3300 | 80 | Olive powder coat | CT-101
CT-L04-S-006 | L04 | CURTAIN_PANEL | Glass | CT-L04-S-006 | L04 | South | Curtain wall | GL1 | 1400 | 3300 | 28 | Blue-grey concept glass | CT-101
CT-L04-S-007 | L04 | CURTAIN_PANEL | Glass | CT-L04-S-007 | L04 | South | Curtain wall | GL1 | 1400 | 3300 | 28 | Blue-grey concept glass | CT-101
CT-L04-S-008 | L04 | CURTAIN_PANEL | Glass | CT-L04-S-008 | L04 | South | Curtain wall | GL1 | 1400 | 3300 | 28 | Blue-grey concept glass | CT-101
CT-L04-S-009 | L04 | CURTAIN_PANEL | Glass | CT-L04-S-009 | L04 | South | Curtain wall | GL1 | 1400 | 3300 | 28 | Blue-grey concept glass | CT-101
CT-L04-S-010 | L04 | SHEET | Aluminium | CT-L04-S-010 | L04 | South | Metal rainscreen | AL2 | 1400 | 3300 | 80 | Olive powder coat | CT-101
CT-L04-S-011 | L04 | CURTAIN_PANEL | Glass | CT-L04-S-011 | L04 | South | Curtain wall | GL1 | 1400 | 3300 | 28 | Blue-grey concept glass | CT-101
CT-L04-S-012 | L04 | CURTAIN_PANEL | Glass | CT-L04-S-012 | L04 | South | Curtain wall | GL1 | 1400 | 3300 | 28 | Blue-grey concept glass | CT-101
CT-L04-S-013 | L04 | CURTAIN_PANEL | Glass | CT-L04-S-013 | L04 | South | Curtain wall | GL1 | 1400 | 3300 | 28 | Blue-grey concept glass | CT-101
CT-L04-S-014 | L04 | CURTAIN_PANEL | Glass | CT-L04-S-014 | L04 | South | Curtain wall | GL1 | 1250 | 3300 | 28 | Blue-grey concept glass | CT-101
CT-L04-E-001 | L04 | CURTAIN_PANEL | Glass | CT-L04-E-001 | L04 | East | Curtain wall | GL1 | 1250 | 3300 | 28 | Blue-grey concept glass | CT-102
CT-L04-E-002 | L04 | CURTAIN_PANEL | Glass | CT-L04-E-002 | L04 | East | Curtain wall | GL1 | 1400 | 3300 | 28 | Blue-grey concept glass | CT-102
CT-L04-E-003 | L04 | CURTAIN_PANEL | Glass | CT-L04-E-003 | L04 | East | Curtain wall | GL1 | 1400 | 3300 | 28 | Blue-grey concept glass | CT-102
CT-L04-E-004 | L04 | CURTAIN_PANEL | Glass | CT-L04-E-004 | L04 | East | Curtain wall | GL1 | 1400 | 3300 | 28 | Blue-grey concept glass | CT-102
CT-L04-E-005 | L04 | SHEET | Aluminium | CT-L04-E-005 | L04 | East | Metal rainscreen | AL2 | 1400 | 3300 | 80 | Olive powder coat | CT-102
CT-L04-E-006 | L04 | CURTAIN_PANEL | Glass | CT-L04-E-006 | L04 | East | Curtain wall | GL1 | 1400 | 3300 | 28 | Blue-grey concept glass | CT-102
CT-L04-E-007 | L04 | CURTAIN_PANEL | Glass | CT-L04-E-007 | L04 | East | Curtain wall | GL1 | 1400 | 3300 | 28 | Blue-grey concept glass | CT-102
CT-L04-E-008 | L04 | CURTAIN_PANEL | Glass | CT-L04-E-008 | L04 | East | Curtain wall | GL1 | 1400 | 3300 | 28 | Blue-grey concept glass | CT-102
CT-L04-E-009 | L04 | CURTAIN_PANEL | Glass | CT-L04-E-009 | L04 | East | Curtain wall | GL1 | 1400 | 3300 | 28 | Blue-grey concept glass | CT-102
CT-L04-E-010 | L04 | SHEET | Aluminium | CT-L04-E-010 | L04 | East | Metal rainscreen | AL2 | 1250 | 3300 | 80 | Olive powder coat | CT-102
CT-L04-N-001 | L04 | CURTAIN_PANEL | Glass | CT-L04-N-001 | L04 | North | Curtain wall | GL1 | 1250 | 3300 | 28 | Blue-grey concept glass | CT-103
CT-L04-N-002 | L04 | CURTAIN_PANEL | Glass | CT-L04-N-002 | L04 | North | Curtain wall | GL1 | 1400 | 3300 | 28 | Blue-grey concept glass | CT-103
CT-L04-N-003 | L04 | CURTAIN_PANEL | Glass | CT-L04-N-003 | L04 | North | Curtain wall | GL1 | 1400 | 3300 | 28 | Blue-grey concept glass | CT-103
CT-L04-N-004 | L04 | CURTAIN_PANEL | Glass | CT-L04-N-004 | L04 | North | Curtain wall | GL1 | 1400 | 3300 | 28 | Blue-grey concept glass | CT-103
CT-L04-N-005 | L04 | SHEET | Aluminium | CT-L04-N-005 | L04 | North | Metal rainscreen | AL2 | 1400 | 3300 | 80 | Olive powder coat | CT-103
CT-L04-N-006 | L04 | CURTAIN_PANEL | Glass | CT-L04-N-006 | L04 | North | Curtain wall | GL1 | 1400 | 3300 | 28 | Blue-grey concept glass | CT-103
CT-L04-N-007 | L04 | CURTAIN_PANEL | Glass | CT-L04-N-007 | L04 | North | Curtain wall | GL1 | 1400 | 3300 | 28 | Blue-grey concept glass | CT-103
CT-L04-N-008 | L04 | CURTAIN_PANEL | Glass | CT-L04-N-008 | L04 | North | Curtain wall | GL1 | 1400 | 3300 | 28 | Blue-grey concept glass | CT-103
CT-L04-N-009 | L04 | CURTAIN_PANEL | Glass | CT-L04-N-009 | L04 | North | Curtain wall | GL1 | 1400 | 3300 | 28 | Blue-grey concept glass | CT-103
CT-L04-N-010 | L04 | SHEET | Aluminium | CT-L04-N-010 | L04 | North | Metal rainscreen | AL2 | 1400 | 3300 | 80 | Olive powder coat | CT-103
CT-L04-N-011 | L04 | CURTAIN_PANEL | Glass | CT-L04-N-011 | L04 | North | Curtain wall | GL1 | 1400 | 3300 | 28 | Blue-grey concept glass | CT-103
CT-L04-N-012 | L04 | CURTAIN_PANEL | Glass | CT-L04-N-012 | L04 | North | Curtain wall | GL1 | 1400 | 3300 | 28 | Blue-grey concept glass | CT-103
CT-L04-N-013 | L04 | CURTAIN_PANEL | Glass | CT-L04-N-013 | L04 | North | Curtain wall | GL1 | 1400 | 3300 | 28 | Blue-grey concept glass | CT-103
CT-L04-N-014 | L04 | CURTAIN_PANEL | Glass | CT-L04-N-014 | L04 | North | Curtain wall | GL1 | 1250 | 3300 | 28 | Blue-grey concept glass | CT-103
CT-L04-W-001 | L04 | CURTAIN_PANEL | Glass | CT-L04-W-001 | L04 | West | Curtain wall | GL1 | 1250 | 3300 | 28 | Blue-grey concept glass | CT-104
CT-L04-W-002 | L04 | CURTAIN_PANEL | Glass | CT-L04-W-002 | L04 | West | Curtain wall | GL1 | 1400 | 3300 | 28 | Blue-grey concept glass | CT-104
CT-L04-W-003 | L04 | CURTAIN_PANEL | Glass | CT-L04-W-003 | L04 | West | Curtain wall | GL1 | 1400 | 3300 | 28 | Blue-grey concept glass | CT-104
CT-L04-W-004 | L04 | CURTAIN_PANEL | Glass | CT-L04-W-004 | L04 | West | Curtain wall | GL1 | 1400 | 3300 | 28 | Blue-grey concept glass | CT-104
CT-L04-W-005 | L04 | SHEET | Aluminium | CT-L04-W-005 | L04 | West | Metal rainscreen | AL2 | 1400 | 3300 | 80 | Olive powder coat | CT-104
CT-L04-W-006 | L04 | CURTAIN_PANEL | Glass | CT-L04-W-006 | L04 | West | Curtain wall | GL1 | 1400 | 3300 | 28 | Blue-grey concept glass | CT-104
CT-L04-W-007 | L04 | CURTAIN_PANEL | Glass | CT-L04-W-007 | L04 | West | Curtain wall | GL1 | 1400 | 3300 | 28 | Blue-grey concept glass | CT-104
CT-L04-W-008 | L04 | CURTAIN_PANEL | Glass | CT-L04-W-008 | L04 | West | Curtain wall | GL1 | 1400 | 3300 | 28 | Blue-grey concept glass | CT-104
CT-L04-W-009 | L04 | CURTAIN_PANEL | Glass | CT-L04-W-009 | L04 | West | Curtain wall | GL1 | 1400 | 3300 | 28 | Blue-grey concept glass | CT-104
CT-L04-W-010 | L04 | SHEET | Aluminium | CT-L04-W-010 | L04 | West | Metal rainscreen | AL2 | 1250 | 3300 | 80 | Olive powder coat | CT-104
CT-L05-S-001 | L05 | CURTAIN_PANEL | Glass | CT-L05-S-001 | L05 | South | Curtain wall | GL1 | 1250 | 3300 | 28 | Blue-grey concept glass | CT-101
CT-L05-S-002 | L05 | CURTAIN_PANEL | Glass | CT-L05-S-002 | L05 | South | Curtain wall | GL1 | 1400 | 3300 | 28 | Blue-grey concept glass | CT-101
CT-L05-S-003 | L05 | CURTAIN_PANEL | Glass | CT-L05-S-003 | L05 | South | Curtain wall | GL1 | 1400 | 3300 | 28 | Blue-grey concept glass | CT-101
CT-L05-S-004 | L05 | CURTAIN_PANEL | Glass | CT-L05-S-004 | L05 | South | Curtain wall | GL1 | 1400 | 3300 | 28 | Blue-grey concept glass | CT-101
CT-L05-S-005 | L05 | SHEET | Aluminium | CT-L05-S-005 | L05 | South | Metal rainscreen | AL2 | 1400 | 3300 | 80 | Olive powder coat | CT-101
CT-L05-S-006 | L05 | CURTAIN_PANEL | Glass | CT-L05-S-006 | L05 | South | Curtain wall | GL1 | 1400 | 3300 | 28 | Blue-grey concept glass | CT-101
CT-L05-S-007 | L05 | CURTAIN_PANEL | Glass | CT-L05-S-007 | L05 | South | Curtain wall | GL1 | 1400 | 3300 | 28 | Blue-grey concept glass | CT-101
CT-L05-S-008 | L05 | CURTAIN_PANEL | Glass | CT-L05-S-008 | L05 | South | Curtain wall | GL1 | 1400 | 3300 | 28 | Blue-grey concept glass | CT-101
CT-L05-S-009 | L05 | CURTAIN_PANEL | Glass | CT-L05-S-009 | L05 | South | Curtain wall | GL1 | 1400 | 3300 | 28 | Blue-grey concept glass | CT-101
CT-L05-S-010 | L05 | SHEET | Aluminium | CT-L05-S-010 | L05 | South | Metal rainscreen | AL2 | 1400 | 3300 | 80 | Olive powder coat | CT-101
CT-L05-S-011 | L05 | CURTAIN_PANEL | Glass | CT-L05-S-011 | L05 | South | Curtain wall | GL1 | 1400 | 3300 | 28 | Blue-grey concept glass | CT-101
CT-L05-S-012 | L05 | CURTAIN_PANEL | Glass | CT-L05-S-012 | L05 | South | Curtain wall | GL1 | 1400 | 3300 | 28 | Blue-grey concept glass | CT-101
CT-L05-S-013 | L05 | CURTAIN_PANEL | Glass | CT-L05-S-013 | L05 | South | Curtain wall | GL1 | 1400 | 3300 | 28 | Blue-grey concept glass | CT-101
CT-L05-S-014 | L05 | CURTAIN_PANEL | Glass | CT-L05-S-014 | L05 | South | Curtain wall | GL1 | 1250 | 3300 | 28 | Blue-grey concept glass | CT-101
CT-L05-E-001 | L05 | CURTAIN_PANEL | Glass | CT-L05-E-001 | L05 | East | Curtain wall | GL1 | 1250 | 3300 | 28 | Blue-grey concept glass | CT-102
CT-L05-E-002 | L05 | CURTAIN_PANEL | Glass | CT-L05-E-002 | L05 | East | Curtain wall | GL1 | 1400 | 3300 | 28 | Blue-grey concept glass | CT-102
CT-L05-E-003 | L05 | CURTAIN_PANEL | Glass | CT-L05-E-003 | L05 | East | Curtain wall | GL1 | 1400 | 3300 | 28 | Blue-grey concept glass | CT-102
CT-L05-E-004 | L05 | CURTAIN_PANEL | Glass | CT-L05-E-004 | L05 | East | Curtain wall | GL1 | 1400 | 3300 | 28 | Blue-grey concept glass | CT-102
CT-L05-E-005 | L05 | SHEET | Aluminium | CT-L05-E-005 | L05 | East | Metal rainscreen | AL2 | 1400 | 3300 | 80 | Olive powder coat | CT-102
CT-L05-E-006 | L05 | CURTAIN_PANEL | Glass | CT-L05-E-006 | L05 | East | Curtain wall | GL1 | 1400 | 3300 | 28 | Blue-grey concept glass | CT-102
CT-L05-E-007 | L05 | CURTAIN_PANEL | Glass | CT-L05-E-007 | L05 | East | Curtain wall | GL1 | 1400 | 3300 | 28 | Blue-grey concept glass | CT-102
CT-L05-E-008 | L05 | CURTAIN_PANEL | Glass | CT-L05-E-008 | L05 | East | Curtain wall | GL1 | 1400 | 3300 | 28 | Blue-grey concept glass | CT-102
CT-L05-E-009 | L05 | CURTAIN_PANEL | Glass | CT-L05-E-009 | L05 | East | Curtain wall | GL1 | 1400 | 3300 | 28 | Blue-grey concept glass | CT-102
CT-L05-E-010 | L05 | SHEET | Aluminium | CT-L05-E-010 | L05 | East | Metal rainscreen | AL2 | 1250 | 3300 | 80 | Olive powder coat | CT-102
CT-L05-N-001 | L05 | CURTAIN_PANEL | Glass | CT-L05-N-001 | L05 | North | Curtain wall | GL1 | 1250 | 3300 | 28 | Blue-grey concept glass | CT-103
CT-L05-N-002 | L05 | CURTAIN_PANEL | Glass | CT-L05-N-002 | L05 | North | Curtain wall | GL1 | 1400 | 3300 | 28 | Blue-grey concept glass | CT-103
CT-L05-N-003 | L05 | CURTAIN_PANEL | Glass | CT-L05-N-003 | L05 | North | Curtain wall | GL1 | 1400 | 3300 | 28 | Blue-grey concept glass | CT-103
CT-L05-N-004 | L05 | CURTAIN_PANEL | Glass | CT-L05-N-004 | L05 | North | Curtain wall | GL1 | 1400 | 3300 | 28 | Blue-grey concept glass | CT-103
CT-L05-N-005 | L05 | SHEET | Aluminium | CT-L05-N-005 | L05 | North | Metal rainscreen | AL2 | 1400 | 3300 | 80 | Olive powder coat | CT-103
CT-L05-N-006 | L05 | CURTAIN_PANEL | Glass | CT-L05-N-006 | L05 | North | Curtain wall | GL1 | 1400 | 3300 | 28 | Blue-grey concept glass | CT-103
CT-L05-N-007 | L05 | CURTAIN_PANEL | Glass | CT-L05-N-007 | L05 | North | Curtain wall | GL1 | 1400 | 3300 | 28 | Blue-grey concept glass | CT-103
CT-L05-N-008 | L05 | CURTAIN_PANEL | Glass | CT-L05-N-008 | L05 | North | Curtain wall | GL1 | 1400 | 3300 | 28 | Blue-grey concept glass | CT-103
CT-L05-N-009 | L05 | CURTAIN_PANEL | Glass | CT-L05-N-009 | L05 | North | Curtain wall | GL1 | 1400 | 3300 | 28 | Blue-grey concept glass | CT-103
CT-L05-N-010 | L05 | SHEET | Aluminium | CT-L05-N-010 | L05 | North | Metal rainscreen | AL2 | 1400 | 3300 | 80 | Olive powder coat | CT-103
CT-L05-N-011 | L05 | CURTAIN_PANEL | Glass | CT-L05-N-011 | L05 | North | Curtain wall | GL1 | 1400 | 3300 | 28 | Blue-grey concept glass | CT-103
CT-L05-N-012 | L05 | CURTAIN_PANEL | Glass | CT-L05-N-012 | L05 | North | Curtain wall | GL1 | 1400 | 3300 | 28 | Blue-grey concept glass | CT-103
CT-L05-N-013 | L05 | CURTAIN_PANEL | Glass | CT-L05-N-013 | L05 | North | Curtain wall | GL1 | 1400 | 3300 | 28 | Blue-grey concept glass | CT-103
CT-L05-N-014 | L05 | CURTAIN_PANEL | Glass | CT-L05-N-014 | L05 | North | Curtain wall | GL1 | 1250 | 3300 | 28 | Blue-grey concept glass | CT-103
CT-L05-W-001 | L05 | CURTAIN_PANEL | Glass | CT-L05-W-001 | L05 | West | Curtain wall | GL1 | 1250 | 3300 | 28 | Blue-grey concept glass | CT-104
CT-L05-W-002 | L05 | CURTAIN_PANEL | Glass | CT-L05-W-002 | L05 | West | Curtain wall | GL1 | 1400 | 3300 | 28 | Blue-grey concept glass | CT-104
CT-L05-W-003 | L05 | CURTAIN_PANEL | Glass | CT-L05-W-003 | L05 | West | Curtain wall | GL1 | 1400 | 3300 | 28 | Blue-grey concept glass | CT-104
CT-L05-W-004 | L05 | CURTAIN_PANEL | Glass | CT-L05-W-004 | L05 | West | Curtain wall | GL1 | 1400 | 3300 | 28 | Blue-grey concept glass | CT-104
CT-L05-W-005 | L05 | SHEET | Aluminium | CT-L05-W-005 | L05 | West | Metal rainscreen | AL2 | 1400 | 3300 | 80 | Olive powder coat | CT-104
CT-L05-W-006 | L05 | CURTAIN_PANEL | Glass | CT-L05-W-006 | L05 | West | Curtain wall | GL1 | 1400 | 3300 | 28 | Blue-grey concept glass | CT-104
CT-L05-W-007 | L05 | CURTAIN_PANEL | Glass | CT-L05-W-007 | L05 | West | Curtain wall | GL1 | 1400 | 3300 | 28 | Blue-grey concept glass | CT-104
CT-L05-W-008 | L05 | CURTAIN_PANEL | Glass | CT-L05-W-008 | L05 | West | Curtain wall | GL1 | 1400 | 3300 | 28 | Blue-grey concept glass | CT-104
CT-L05-W-009 | L05 | CURTAIN_PANEL | Glass | CT-L05-W-009 | L05 | West | Curtain wall | GL1 | 1400 | 3300 | 28 | Blue-grey concept glass | CT-104
CT-L05-W-010 | L05 | SHEET | Aluminium | CT-L05-W-010 | L05 | West | Metal rainscreen | AL2 | 1250 | 3300 | 80 | Olive powder coat | CT-104
CT-L06-S-001 | L06 | CURTAIN_PANEL | Glass | CT-L06-S-001 | L06 | South | Curtain wall | GL1 | 1250 | 3300 | 28 | Blue-grey concept glass | CT-101
CT-L06-S-002 | L06 | CURTAIN_PANEL | Glass | CT-L06-S-002 | L06 | South | Curtain wall | GL1 | 1400 | 3300 | 28 | Blue-grey concept glass | CT-101
CT-L06-S-003 | L06 | CURTAIN_PANEL | Glass | CT-L06-S-003 | L06 | South | Curtain wall | GL1 | 1400 | 3300 | 28 | Blue-grey concept glass | CT-101
CT-L06-S-004 | L06 | CURTAIN_PANEL | Glass | CT-L06-S-004 | L06 | South | Curtain wall | GL1 | 1400 | 3300 | 28 | Blue-grey concept glass | CT-101
CT-L06-S-005 | L06 | SHEET | Aluminium | CT-L06-S-005 | L06 | South | Metal rainscreen | AL2 | 1400 | 3300 | 80 | Olive powder coat | CT-101
CT-L06-S-006 | L06 | CURTAIN_PANEL | Glass | CT-L06-S-006 | L06 | South | Curtain wall | GL1 | 1400 | 3300 | 28 | Blue-grey concept glass | CT-101
CT-L06-S-007 | L06 | CURTAIN_PANEL | Glass | CT-L06-S-007 | L06 | South | Curtain wall | GL1 | 1400 | 3300 | 28 | Blue-grey concept glass | CT-101
CT-L06-S-008 | L06 | CURTAIN_PANEL | Glass | CT-L06-S-008 | L06 | South | Curtain wall | GL1 | 1400 | 3300 | 28 | Blue-grey concept glass | CT-101
CT-L06-S-009 | L06 | CURTAIN_PANEL | Glass | CT-L06-S-009 | L06 | South | Curtain wall | GL1 | 1400 | 3300 | 28 | Blue-grey concept glass | CT-101
CT-L06-S-010 | L06 | SHEET | Aluminium | CT-L06-S-010 | L06 | South | Metal rainscreen | AL2 | 1400 | 3300 | 80 | Olive powder coat | CT-101
CT-L06-S-011 | L06 | CURTAIN_PANEL | Glass | CT-L06-S-011 | L06 | South | Curtain wall | GL1 | 1400 | 3300 | 28 | Blue-grey concept glass | CT-101
CT-L06-S-012 | L06 | CURTAIN_PANEL | Glass | CT-L06-S-012 | L06 | South | Curtain wall | GL1 | 1400 | 3300 | 28 | Blue-grey concept glass | CT-101
CT-L06-S-013 | L06 | CURTAIN_PANEL | Glass | CT-L06-S-013 | L06 | South | Curtain wall | GL1 | 1400 | 3300 | 28 | Blue-grey concept glass | CT-101
CT-L06-S-014 | L06 | CURTAIN_PANEL | Glass | CT-L06-S-014 | L06 | South | Curtain wall | GL1 | 1250 | 3300 | 28 | Blue-grey concept glass | CT-101
CT-L06-E-001 | L06 | CURTAIN_PANEL | Glass | CT-L06-E-001 | L06 | East | Curtain wall | GL1 | 1250 | 3300 | 28 | Blue-grey concept glass | CT-102
CT-L06-E-002 | L06 | CURTAIN_PANEL | Glass | CT-L06-E-002 | L06 | East | Curtain wall | GL1 | 1400 | 3300 | 28 | Blue-grey concept glass | CT-102
CT-L06-E-003 | L06 | CURTAIN_PANEL | Glass | CT-L06-E-003 | L06 | East | Curtain wall | GL1 | 1400 | 3300 | 28 | Blue-grey concept glass | CT-102
CT-L06-E-004 | L06 | CURTAIN_PANEL | Glass | CT-L06-E-004 | L06 | East | Curtain wall | GL1 | 1400 | 3300 | 28 | Blue-grey concept glass | CT-102
CT-L06-E-005 | L06 | SHEET | Aluminium | CT-L06-E-005 | L06 | East | Metal rainscreen | AL2 | 1400 | 3300 | 80 | Olive powder coat | CT-102
CT-L06-E-006 | L06 | CURTAIN_PANEL | Glass | CT-L06-E-006 | L06 | East | Curtain wall | GL1 | 1400 | 3300 | 28 | Blue-grey concept glass | CT-102
CT-L06-E-007 | L06 | CURTAIN_PANEL | Glass | CT-L06-E-007 | L06 | East | Curtain wall | GL1 | 1400 | 3300 | 28 | Blue-grey concept glass | CT-102
CT-L06-E-008 | L06 | CURTAIN_PANEL | Glass | CT-L06-E-008 | L06 | East | Curtain wall | GL1 | 1400 | 3300 | 28 | Blue-grey concept glass | CT-102
CT-L06-E-009 | L06 | CURTAIN_PANEL | Glass | CT-L06-E-009 | L06 | East | Curtain wall | GL1 | 1400 | 3300 | 28 | Blue-grey concept glass | CT-102
CT-L06-E-010 | L06 | SHEET | Aluminium | CT-L06-E-010 | L06 | East | Metal rainscreen | AL2 | 1250 | 3300 | 80 | Olive powder coat | CT-102
CT-L06-N-001 | L06 | CURTAIN_PANEL | Glass | CT-L06-N-001 | L06 | North | Curtain wall | GL1 | 1250 | 3300 | 28 | Blue-grey concept glass | CT-103
CT-L06-N-002 | L06 | CURTAIN_PANEL | Glass | CT-L06-N-002 | L06 | North | Curtain wall | GL1 | 1400 | 3300 | 28 | Blue-grey concept glass | CT-103
CT-L06-N-003 | L06 | CURTAIN_PANEL | Glass | CT-L06-N-003 | L06 | North | Curtain wall | GL1 | 1400 | 3300 | 28 | Blue-grey concept glass | CT-103
CT-L06-N-004 | L06 | CURTAIN_PANEL | Glass | CT-L06-N-004 | L06 | North | Curtain wall | GL1 | 1400 | 3300 | 28 | Blue-grey concept glass | CT-103
CT-L06-N-005 | L06 | SHEET | Aluminium | CT-L06-N-005 | L06 | North | Metal rainscreen | AL2 | 1400 | 3300 | 80 | Olive powder coat | CT-103
CT-L06-N-006 | L06 | CURTAIN_PANEL | Glass | CT-L06-N-006 | L06 | North | Curtain wall | GL1 | 1400 | 3300 | 28 | Blue-grey concept glass | CT-103
CT-L06-N-007 | L06 | CURTAIN_PANEL | Glass | CT-L06-N-007 | L06 | North | Curtain wall | GL1 | 1400 | 3300 | 28 | Blue-grey concept glass | CT-103
CT-L06-N-008 | L06 | CURTAIN_PANEL | Glass | CT-L06-N-008 | L06 | North | Curtain wall | GL1 | 1400 | 3300 | 28 | Blue-grey concept glass | CT-103
CT-L06-N-009 | L06 | CURTAIN_PANEL | Glass | CT-L06-N-009 | L06 | North | Curtain wall | GL1 | 1400 | 3300 | 28 | Blue-grey concept glass | CT-103
CT-L06-N-010 | L06 | SHEET | Aluminium | CT-L06-N-010 | L06 | North | Metal rainscreen | AL2 | 1400 | 3300 | 80 | Olive powder coat | CT-103
CT-L06-N-011 | L06 | CURTAIN_PANEL | Glass | CT-L06-N-011 | L06 | North | Curtain wall | GL1 | 1400 | 3300 | 28 | Blue-grey concept glass | CT-103
CT-L06-N-012 | L06 | CURTAIN_PANEL | Glass | CT-L06-N-012 | L06 | North | Curtain wall | GL1 | 1400 | 3300 | 28 | Blue-grey concept glass | CT-103
CT-L06-N-013 | L06 | CURTAIN_PANEL | Glass | CT-L06-N-013 | L06 | North | Curtain wall | GL1 | 1400 | 3300 | 28 | Blue-grey concept glass | CT-103
CT-L06-N-014 | L06 | CURTAIN_PANEL | Glass | CT-L06-N-014 | L06 | North | Curtain wall | GL1 | 1250 | 3300 | 28 | Blue-grey concept glass | CT-103
CT-L06-W-001 | L06 | CURTAIN_PANEL | Glass | CT-L06-W-001 | L06 | West | Curtain wall | GL1 | 1250 | 3300 | 28 | Blue-grey concept glass | CT-104
CT-L06-W-002 | L06 | CURTAIN_PANEL | Glass | CT-L06-W-002 | L06 | West | Curtain wall | GL1 | 1400 | 3300 | 28 | Blue-grey concept glass | CT-104
CT-L06-W-003 | L06 | CURTAIN_PANEL | Glass | CT-L06-W-003 | L06 | West | Curtain wall | GL1 | 1400 | 3300 | 28 | Blue-grey concept glass | CT-104
CT-L06-W-004 | L06 | CURTAIN_PANEL | Glass | CT-L06-W-004 | L06 | West | Curtain wall | GL1 | 1400 | 3300 | 28 | Blue-grey concept glass | CT-104
CT-L06-W-005 | L06 | SHEET | Aluminium | CT-L06-W-005 | L06 | West | Metal rainscreen | AL2 | 1400 | 3300 | 80 | Olive powder coat | CT-104
CT-L06-W-006 | L06 | CURTAIN_PANEL | Glass | CT-L06-W-006 | L06 | West | Curtain wall | GL1 | 1400 | 3300 | 28 | Blue-grey concept glass | CT-104
CT-L06-W-007 | L06 | CURTAIN_PANEL | Glass | CT-L06-W-007 | L06 | West | Curtain wall | GL1 | 1400 | 3300 | 28 | Blue-grey concept glass | CT-104
CT-L06-W-008 | L06 | CURTAIN_PANEL | Glass | CT-L06-W-008 | L06 | West | Curtain wall | GL1 | 1400 | 3300 | 28 | Blue-grey concept glass | CT-104
CT-L06-W-009 | L06 | CURTAIN_PANEL | Glass | CT-L06-W-009 | L06 | West | Curtain wall | GL1 | 1400 | 3300 | 28 | Blue-grey concept glass | CT-104
CT-L06-W-010 | L06 | SHEET | Aluminium | CT-L06-W-010 | L06 | West | Metal rainscreen | AL2 | 1250 | 3300 | 80 | Olive powder coat | CT-104
CT-L07-S-001 | L07 | CURTAIN_PANEL | Glass | CT-L07-S-001 | L07 | South | Curtain wall | GL1 | 1250 | 3300 | 28 | Blue-grey concept glass | CT-101
CT-L07-S-002 | L07 | CURTAIN_PANEL | Glass | CT-L07-S-002 | L07 | South | Curtain wall | GL1 | 1400 | 3300 | 28 | Blue-grey concept glass | CT-101
CT-L07-S-003 | L07 | CURTAIN_PANEL | Glass | CT-L07-S-003 | L07 | South | Curtain wall | GL1 | 1400 | 3300 | 28 | Blue-grey concept glass | CT-101
CT-L07-S-004 | L07 | CURTAIN_PANEL | Glass | CT-L07-S-004 | L07 | South | Curtain wall | GL1 | 1400 | 3300 | 28 | Blue-grey concept glass | CT-101
CT-L07-S-005 | L07 | SHEET | Aluminium | CT-L07-S-005 | L07 | South | Metal rainscreen | AL2 | 1400 | 3300 | 80 | Olive powder coat | CT-101
CT-L07-S-006 | L07 | CURTAIN_PANEL | Glass | CT-L07-S-006 | L07 | South | Curtain wall | GL1 | 1400 | 3300 | 28 | Blue-grey concept glass | CT-101
CT-L07-S-007 | L07 | CURTAIN_PANEL | Glass | CT-L07-S-007 | L07 | South | Curtain wall | GL1 | 1400 | 3300 | 28 | Blue-grey concept glass | CT-101
CT-L07-S-008 | L07 | CURTAIN_PANEL | Glass | CT-L07-S-008 | L07 | South | Curtain wall | GL1 | 1400 | 3300 | 28 | Blue-grey concept glass | CT-101
CT-L07-S-009 | L07 | CURTAIN_PANEL | Glass | CT-L07-S-009 | L07 | South | Curtain wall | GL1 | 1400 | 3300 | 28 | Blue-grey concept glass | CT-101
CT-L07-S-010 | L07 | SHEET | Aluminium | CT-L07-S-010 | L07 | South | Metal rainscreen | AL2 | 1400 | 3300 | 80 | Olive powder coat | CT-101
CT-L07-S-011 | L07 | CURTAIN_PANEL | Glass | CT-L07-S-011 | L07 | South | Curtain wall | GL1 | 1400 | 3300 | 28 | Blue-grey concept glass | CT-101
CT-L07-S-012 | L07 | CURTAIN_PANEL | Glass | CT-L07-S-012 | L07 | South | Curtain wall | GL1 | 1400 | 3300 | 28 | Blue-grey concept glass | CT-101
CT-L07-S-013 | L07 | CURTAIN_PANEL | Glass | CT-L07-S-013 | L07 | South | Curtain wall | GL1 | 1400 | 3300 | 28 | Blue-grey concept glass | CT-101
CT-L07-S-014 | L07 | CURTAIN_PANEL | Glass | CT-L07-S-014 | L07 | South | Curtain wall | GL1 | 1250 | 3300 | 28 | Blue-grey concept glass | CT-101
CT-L07-E-001 | L07 | CURTAIN_PANEL | Glass | CT-L07-E-001 | L07 | East | Curtain wall | GL1 | 1250 | 3300 | 28 | Blue-grey concept glass | CT-102
CT-L07-E-002 | L07 | CURTAIN_PANEL | Glass | CT-L07-E-002 | L07 | East | Curtain wall | GL1 | 1400 | 3300 | 28 | Blue-grey concept glass | CT-102
CT-L07-E-003 | L07 | CURTAIN_PANEL | Glass | CT-L07-E-003 | L07 | East | Curtain wall | GL1 | 1400 | 3300 | 28 | Blue-grey concept glass | CT-102
CT-L07-E-004 | L07 | CURTAIN_PANEL | Glass | CT-L07-E-004 | L07 | East | Curtain wall | GL1 | 1400 | 3300 | 28 | Blue-grey concept glass | CT-102
CT-L07-E-005 | L07 | SHEET | Aluminium | CT-L07-E-005 | L07 | East | Metal rainscreen | AL2 | 1400 | 3300 | 80 | Olive powder coat | CT-102
CT-L07-E-006 | L07 | CURTAIN_PANEL | Glass | CT-L07-E-006 | L07 | East | Curtain wall | GL1 | 1400 | 3300 | 28 | Blue-grey concept glass | CT-102
CT-L07-E-007 | L07 | CURTAIN_PANEL | Glass | CT-L07-E-007 | L07 | East | Curtain wall | GL1 | 1400 | 3300 | 28 | Blue-grey concept glass | CT-102
CT-L07-E-008 | L07 | CURTAIN_PANEL | Glass | CT-L07-E-008 | L07 | East | Curtain wall | GL1 | 1400 | 3300 | 28 | Blue-grey concept glass | CT-102
CT-L07-E-009 | L07 | CURTAIN_PANEL | Glass | CT-L07-E-009 | L07 | East | Curtain wall | GL1 | 1400 | 3300 | 28 | Blue-grey concept glass | CT-102
CT-L07-E-010 | L07 | SHEET | Aluminium | CT-L07-E-010 | L07 | East | Metal rainscreen | AL2 | 1250 | 3300 | 80 | Olive powder coat | CT-102
CT-L07-N-001 | L07 | CURTAIN_PANEL | Glass | CT-L07-N-001 | L07 | North | Curtain wall | GL1 | 1250 | 3300 | 28 | Blue-grey concept glass | CT-103
CT-L07-N-002 | L07 | CURTAIN_PANEL | Glass | CT-L07-N-002 | L07 | North | Curtain wall | GL1 | 1400 | 3300 | 28 | Blue-grey concept glass | CT-103
CT-L07-N-003 | L07 | CURTAIN_PANEL | Glass | CT-L07-N-003 | L07 | North | Curtain wall | GL1 | 1400 | 3300 | 28 | Blue-grey concept glass | CT-103
CT-L07-N-004 | L07 | CURTAIN_PANEL | Glass | CT-L07-N-004 | L07 | North | Curtain wall | GL1 | 1400 | 3300 | 28 | Blue-grey concept glass | CT-103
CT-L07-N-005 | L07 | SHEET | Aluminium | CT-L07-N-005 | L07 | North | Metal rainscreen | AL2 | 1400 | 3300 | 80 | Olive powder coat | CT-103
CT-L07-N-006 | L07 | CURTAIN_PANEL | Glass | CT-L07-N-006 | L07 | North | Curtain wall | GL1 | 1400 | 3300 | 28 | Blue-grey concept glass | CT-103
CT-L07-N-007 | L07 | CURTAIN_PANEL | Glass | CT-L07-N-007 | L07 | North | Curtain wall | GL1 | 1400 | 3300 | 28 | Blue-grey concept glass | CT-103
CT-L07-N-008 | L07 | CURTAIN_PANEL | Glass | CT-L07-N-008 | L07 | North | Curtain wall | GL1 | 1400 | 3300 | 28 | Blue-grey concept glass | CT-103
CT-L07-N-009 | L07 | CURTAIN_PANEL | Glass | CT-L07-N-009 | L07 | North | Curtain wall | GL1 | 1400 | 3300 | 28 | Blue-grey concept glass | CT-103
CT-L07-N-010 | L07 | SHEET | Aluminium | CT-L07-N-010 | L07 | North | Metal rainscreen | AL2 | 1400 | 3300 | 80 | Olive powder coat | CT-103
CT-L07-N-011 | L07 | CURTAIN_PANEL | Glass | CT-L07-N-011 | L07 | North | Curtain wall | GL1 | 1400 | 3300 | 28 | Blue-grey concept glass | CT-103
CT-L07-N-012 | L07 | CURTAIN_PANEL | Glass | CT-L07-N-012 | L07 | North | Curtain wall | GL1 | 1400 | 3300 | 28 | Blue-grey concept glass | CT-103
CT-L07-N-013 | L07 | CURTAIN_PANEL | Glass | CT-L07-N-013 | L07 | North | Curtain wall | GL1 | 1400 | 3300 | 28 | Blue-grey concept glass | CT-103
CT-L07-N-014 | L07 | CURTAIN_PANEL | Glass | CT-L07-N-014 | L07 | North | Curtain wall | GL1 | 1250 | 3300 | 28 | Blue-grey concept glass | CT-103
CT-L07-W-001 | L07 | CURTAIN_PANEL | Glass | CT-L07-W-001 | L07 | West | Curtain wall | GL1 | 1250 | 3300 | 28 | Blue-grey concept glass | CT-104
CT-L07-W-002 | L07 | CURTAIN_PANEL | Glass | CT-L07-W-002 | L07 | West | Curtain wall | GL1 | 1400 | 3300 | 28 | Blue-grey concept glass | CT-104
CT-L07-W-003 | L07 | CURTAIN_PANEL | Glass | CT-L07-W-003 | L07 | West | Curtain wall | GL1 | 1400 | 3300 | 28 | Blue-grey concept glass | CT-104
CT-L07-W-004 | L07 | CURTAIN_PANEL | Glass | CT-L07-W-004 | L07 | West | Curtain wall | GL1 | 1400 | 3300 | 28 | Blue-grey concept glass | CT-104
CT-L07-W-005 | L07 | SHEET | Aluminium | CT-L07-W-005 | L07 | West | Metal rainscreen | AL2 | 1400 | 3300 | 80 | Olive powder coat | CT-104
CT-L07-W-006 | L07 | CURTAIN_PANEL | Glass | CT-L07-W-006 | L07 | West | Curtain wall | GL1 | 1400 | 3300 | 28 | Blue-grey concept glass | CT-104
CT-L07-W-007 | L07 | CURTAIN_PANEL | Glass | CT-L07-W-007 | L07 | West | Curtain wall | GL1 | 1400 | 3300 | 28 | Blue-grey concept glass | CT-104
CT-L07-W-008 | L07 | CURTAIN_PANEL | Glass | CT-L07-W-008 | L07 | West | Curtain wall | GL1 | 1400 | 3300 | 28 | Blue-grey concept glass | CT-104
CT-L07-W-009 | L07 | CURTAIN_PANEL | Glass | CT-L07-W-009 | L07 | West | Curtain wall | GL1 | 1400 | 3300 | 28 | Blue-grey concept glass | CT-104
CT-L07-W-010 | L07 | SHEET | Aluminium | CT-L07-W-010 | L07 | West | Metal rainscreen | AL2 | 1250 | 3300 | 80 | Olive powder coat | CT-104
CT-L08-S-001 | L08 | CURTAIN_PANEL | Glass | CT-L08-S-001 | L08 | South | Curtain wall | GL1 | 1250 | 3300 | 28 | Blue-grey concept glass | CT-101
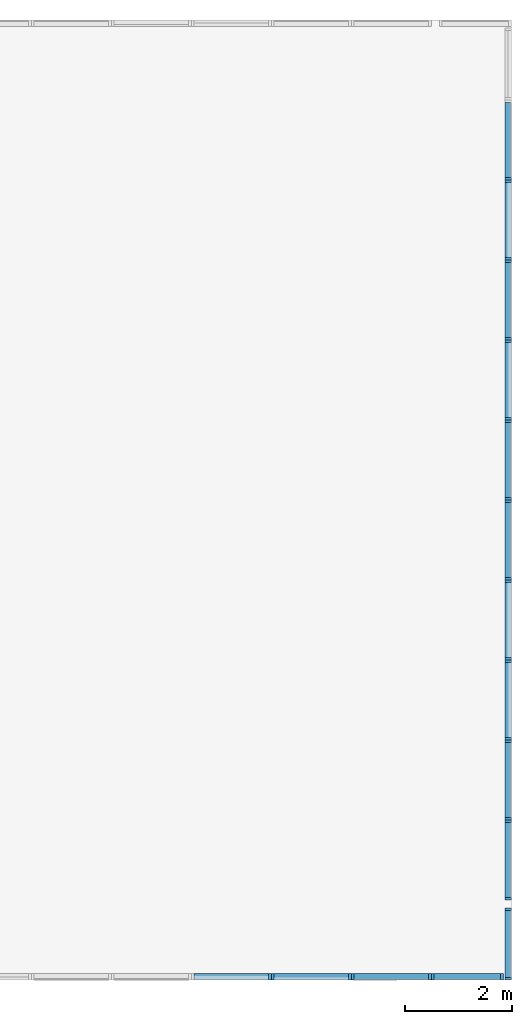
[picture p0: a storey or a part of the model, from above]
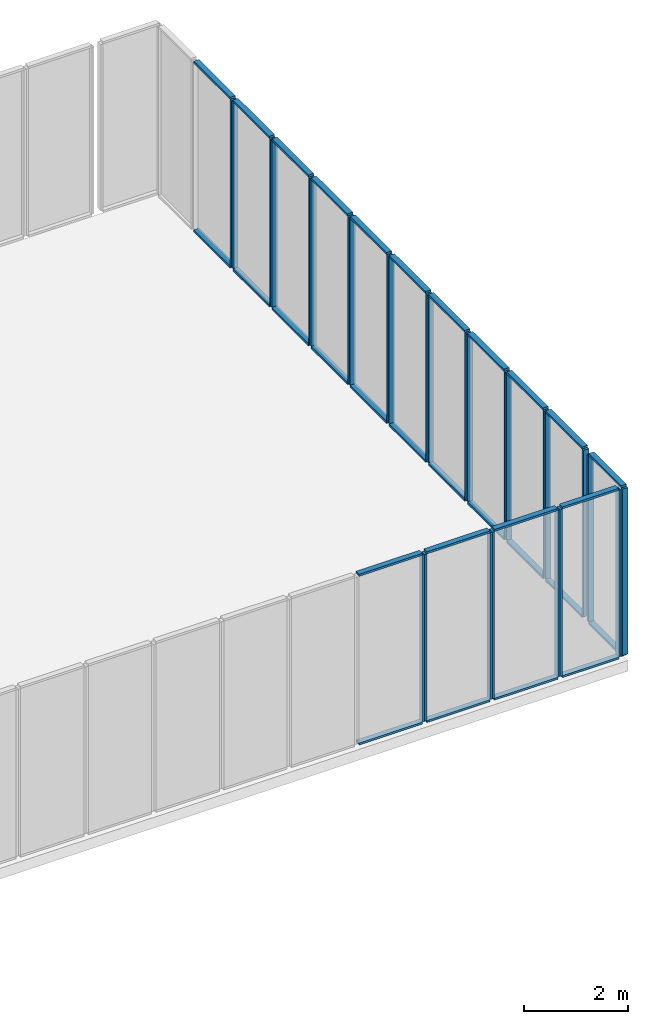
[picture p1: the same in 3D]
Properties of the parts of a building model (IFC4), part 7 of 7

# IfcPlate (576)
Name | In | PredefinedType | Material | ElementID | Floor | Elevation | System = Group | TypeCode | Width_mm | Height_mm | Thickness_mm | Finish | DrawingRef
CT-L08-S-002 | L08 | CURTAIN_PANEL | Glass | CT-L08-S-002 | L08 | South | Curtain wall | GL1 | 1400 | 3300 | 28 | Blue-grey concept glass | CT-101
CT-L08-S-003 | L08 | CURTAIN_PANEL | Glass | CT-L08-S-003 | L08 | South | Curtain wall | GL1 | 1400 | 3300 | 28 | Blue-grey concept glass | CT-101
CT-L08-S-004 | L08 | CURTAIN_PANEL | Glass | CT-L08-S-004 | L08 | South | Curtain wall | GL1 | 1400 | 3300 | 28 | Blue-grey concept glass | CT-101
CT-L08-S-005 | L08 | SHEET | Aluminium | CT-L08-S-005 | L08 | South | Metal rainscreen | AL2 | 1400 | 3300 | 80 | Olive powder coat | CT-101
CT-L08-S-006 | L08 | CURTAIN_PANEL | Glass | CT-L08-S-006 | L08 | South | Curtain wall | GL1 | 1400 | 3300 | 28 | Blue-grey concept glass | CT-101
CT-L08-S-007 | L08 | CURTAIN_PANEL | Glass | CT-L08-S-007 | L08 | South | Curtain wall | GL1 | 1400 | 3300 | 28 | Blue-grey concept glass | CT-101
CT-L08-S-008 | L08 | CURTAIN_PANEL | Glass | CT-L08-S-008 | L08 | South | Curtain wall | GL1 | 1400 | 3300 | 28 | Blue-grey concept glass | CT-101
CT-L08-S-009 | L08 | CURTAIN_PANEL | Glass | CT-L08-S-009 | L08 | South | Curtain wall | GL1 | 1400 | 3300 | 28 | Blue-grey concept glass | CT-101
CT-L08-S-010 | L08 | SHEET | Aluminium | CT-L08-S-010 | L08 | South | Metal rainscreen | AL2 | 1400 | 3300 | 80 | Olive powder coat | CT-101
CT-L08-S-011 | L08 | CURTAIN_PANEL | Glass | CT-L08-S-011 | L08 | South | Curtain wall | GL1 | 1400 | 3300 | 28 | Blue-grey concept glass | CT-101
CT-L08-S-012 | L08 | CURTAIN_PANEL | Glass | CT-L08-S-012 | L08 | South | Curtain wall | GL1 | 1400 | 3300 | 28 | Blue-grey concept glass | CT-101
CT-L08-S-013 | L08 | CURTAIN_PANEL | Glass | CT-L08-S-013 | L08 | South | Curtain wall | GL1 | 1400 | 3300 | 28 | Blue-grey concept glass | CT-101
CT-L08-S-014 | L08 | CURTAIN_PANEL | Glass | CT-L08-S-014 | L08 | South | Curtain wall | GL1 | 1250 | 3300 | 28 | Blue-grey concept glass | CT-101
CT-L08-E-001 | L08 | CURTAIN_PANEL | Glass | CT-L08-E-001 | L08 | East | Curtain wall | GL1 | 1250 | 3300 | 28 | Blue-grey concept glass | CT-102
CT-L08-E-002 | L08 | CURTAIN_PANEL | Glass | CT-L08-E-002 | L08 | East | Curtain wall | GL1 | 1400 | 3300 | 28 | Blue-grey concept glass | CT-102
CT-L08-E-003 | L08 | CURTAIN_PANEL | Glass | CT-L08-E-003 | L08 | East | Curtain wall | GL1 | 1400 | 3300 | 28 | Blue-grey concept glass | CT-102
CT-L08-E-004 | L08 | CURTAIN_PANEL | Glass | CT-L08-E-004 | L08 | East | Curtain wall | GL1 | 1400 | 3300 | 28 | Blue-grey concept glass | CT-102
CT-L08-E-005 | L08 | SHEET | Aluminium | CT-L08-E-005 | L08 | East | Metal rainscreen | AL2 | 1400 | 3300 | 80 | Olive powder coat | CT-102
CT-L08-E-006 | L08 | CURTAIN_PANEL | Glass | CT-L08-E-006 | L08 | East | Curtain wall | GL1 | 1400 | 3300 | 28 | Blue-grey concept glass | CT-102
CT-L08-E-007 | L08 | CURTAIN_PANEL | Glass | CT-L08-E-007 | L08 | East | Curtain wall | GL1 | 1400 | 3300 | 28 | Blue-grey concept glass | CT-102
CT-L08-E-008 | L08 | CURTAIN_PANEL | Glass | CT-L08-E-008 | L08 | East | Curtain wall | GL1 | 1400 | 3300 | 28 | Blue-grey concept glass | CT-102
CT-L08-E-009 | L08 | CURTAIN_PANEL | Glass | CT-L08-E-009 | L08 | East | Curtain wall | GL1 | 1400 | 3300 | 28 | Blue-grey concept glass | CT-102
CT-L08-E-010 | L08 | SHEET | Aluminium | CT-L08-E-010 | L08 | East | Metal rainscreen | AL2 | 1250 | 3300 | 80 | Olive powder coat | CT-102
CT-L08-N-001 | L08 | CURTAIN_PANEL | Glass | CT-L08-N-001 | L08 | North | Curtain wall | GL1 | 1250 | 3300 | 28 | Blue-grey concept glass | CT-103
CT-L08-N-002 | L08 | CURTAIN_PANEL | Glass | CT-L08-N-002 | L08 | North | Curtain wall | GL1 | 1400 | 3300 | 28 | Blue-grey concept glass | CT-103
CT-L08-N-003 | L08 | CURTAIN_PANEL | Glass | CT-L08-N-003 | L08 | North | Curtain wall | GL1 | 1400 | 3300 | 28 | Blue-grey concept glass | CT-103
CT-L08-N-004 | L08 | CURTAIN_PANEL | Glass | CT-L08-N-004 | L08 | North | Curtain wall | GL1 | 1400 | 3300 | 28 | Blue-grey concept glass | CT-103
CT-L08-N-005 | L08 | SHEET | Aluminium | CT-L08-N-005 | L08 | North | Metal rainscreen | AL2 | 1400 | 3300 | 80 | Olive powder coat | CT-103
CT-L08-N-006 | L08 | CURTAIN_PANEL | Glass | CT-L08-N-006 | L08 | North | Curtain wall | GL1 | 1400 | 3300 | 28 | Blue-grey concept glass | CT-103
CT-L08-N-007 | L08 | CURTAIN_PANEL | Glass | CT-L08-N-007 | L08 | North | Curtain wall | GL1 | 1400 | 3300 | 28 | Blue-grey concept glass | CT-103
CT-L08-N-008 | L08 | CURTAIN_PANEL | Glass | CT-L08-N-008 | L08 | North | Curtain wall | GL1 | 1400 | 3300 | 28 | Blue-grey concept glass | CT-103
CT-L08-N-009 | L08 | CURTAIN_PANEL | Glass | CT-L08-N-009 | L08 | North | Curtain wall | GL1 | 1400 | 3300 | 28 | Blue-grey concept glass | CT-103
CT-L08-N-010 | L08 | SHEET | Aluminium | CT-L08-N-010 | L08 | North | Metal rainscreen | AL2 | 1400 | 3300 | 80 | Olive powder coat | CT-103
CT-L08-N-011 | L08 | CURTAIN_PANEL | Glass | CT-L08-N-011 | L08 | North | Curtain wall | GL1 | 1400 | 3300 | 28 | Blue-grey concept glass | CT-103
CT-L08-N-012 | L08 | CURTAIN_PANEL | Glass | CT-L08-N-012 | L08 | North | Curtain wall | GL1 | 1400 | 3300 | 28 | Blue-grey concept glass | CT-103
CT-L08-N-013 | L08 | CURTAIN_PANEL | Glass | CT-L08-N-013 | L08 | North | Curtain wall | GL1 | 1400 | 3300 | 28 | Blue-grey concept glass | CT-103
CT-L08-N-014 | L08 | CURTAIN_PANEL | Glass | CT-L08-N-014 | L08 | North | Curtain wall | GL1 | 1250 | 3300 | 28 | Blue-grey concept glass | CT-103
CT-L08-W-001 | L08 | CURTAIN_PANEL | Glass | CT-L08-W-001 | L08 | West | Curtain wall | GL1 | 1250 | 3300 | 28 | Blue-grey concept glass | CT-104
CT-L08-W-002 | L08 | CURTAIN_PANEL | Glass | CT-L08-W-002 | L08 | West | Curtain wall | GL1 | 1400 | 3300 | 28 | Blue-grey concept glass | CT-104
CT-L08-W-003 | L08 | CURTAIN_PANEL | Glass | CT-L08-W-003 | L08 | West | Curtain wall | GL1 | 1400 | 3300 | 28 | Blue-grey concept glass | CT-104
CT-L08-W-004 | L08 | CURTAIN_PANEL | Glass | CT-L08-W-004 | L08 | West | Curtain wall | GL1 | 1400 | 3300 | 28 | Blue-grey concept glass | CT-104
CT-L08-W-005 | L08 | SHEET | Aluminium | CT-L08-W-005 | L08 | West | Metal rainscreen | AL2 | 1400 | 3300 | 80 | Olive powder coat | CT-104
CT-L08-W-006 | L08 | CURTAIN_PANEL | Glass | CT-L08-W-006 | L08 | West | Curtain wall | GL1 | 1400 | 3300 | 28 | Blue-grey concept glass | CT-104
CT-L08-W-007 | L08 | CURTAIN_PANEL | Glass | CT-L08-W-007 | L08 | West | Curtain wall | GL1 | 1400 | 3300 | 28 | Blue-grey concept glass | CT-104
CT-L08-W-008 | L08 | CURTAIN_PANEL | Glass | CT-L08-W-008 | L08 | West | Curtain wall | GL1 | 1400 | 3300 | 28 | Blue-grey concept glass | CT-104
CT-L08-W-009 | L08 | CURTAIN_PANEL | Glass | CT-L08-W-009 | L08 | West | Curtain wall | GL1 | 1400 | 3300 | 28 | Blue-grey concept glass | CT-104
CT-L08-W-010 | L08 | SHEET | Aluminium | CT-L08-W-010 | L08 | West | Metal rainscreen | AL2 | 1250 | 3300 | 80 | Olive powder coat | CT-104
CT-L09-S-001 | L09 | CURTAIN_PANEL | Glass | CT-L09-S-001 | L09 | South | Curtain wall | GL1 | 1250 | 3300 | 28 | Blue-grey concept glass | CT-101
CT-L09-S-002 | L09 | CURTAIN_PANEL | Glass | CT-L09-S-002 | L09 | South | Curtain wall | GL1 | 1400 | 3300 | 28 | Blue-grey concept glass | CT-101
CT-L09-S-003 | L09 | CURTAIN_PANEL | Glass | CT-L09-S-003 | L09 | South | Curtain wall | GL1 | 1400 | 3300 | 28 | Blue-grey concept glass | CT-101
CT-L09-S-004 | L09 | CURTAIN_PANEL | Glass | CT-L09-S-004 | L09 | South | Curtain wall | GL1 | 1400 | 3300 | 28 | Blue-grey concept glass | CT-101
CT-L09-S-005 | L09 | SHEET | Aluminium | CT-L09-S-005 | L09 | South | Metal rainscreen | AL2 | 1400 | 3300 | 80 | Olive powder coat | CT-101
CT-L09-S-006 | L09 | CURTAIN_PANEL | Glass | CT-L09-S-006 | L09 | South | Curtain wall | GL1 | 1400 | 3300 | 28 | Blue-grey concept glass | CT-101
CT-L09-S-007 | L09 | CURTAIN_PANEL | Glass | CT-L09-S-007 | L09 | South | Curtain wall | GL1 | 1400 | 3300 | 28 | Blue-grey concept glass | CT-101
CT-L09-S-008 | L09 | CURTAIN_PANEL | Glass | CT-L09-S-008 | L09 | South | Curtain wall | GL1 | 1400 | 3300 | 28 | Blue-grey concept glass | CT-101
CT-L09-S-009 | L09 | CURTAIN_PANEL | Glass | CT-L09-S-009 | L09 | South | Curtain wall | GL1 | 1400 | 3300 | 28 | Blue-grey concept glass | CT-101
CT-L09-S-010 | L09 | SHEET | Aluminium | CT-L09-S-010 | L09 | South | Metal rainscreen | AL2 | 1400 | 3300 | 80 | Olive powder coat | CT-101
CT-L09-S-011 | L09 | CURTAIN_PANEL | Glass | CT-L09-S-011 | L09 | South | Curtain wall | GL1 | 1400 | 3300 | 28 | Blue-grey concept glass | CT-101
CT-L09-S-012 | L09 | CURTAIN_PANEL | Glass | CT-L09-S-012 | L09 | South | Curtain wall | GL1 | 1400 | 3300 | 28 | Blue-grey concept glass | CT-101
CT-L09-S-013 | L09 | CURTAIN_PANEL | Glass | CT-L09-S-013 | L09 | South | Curtain wall | GL1 | 1400 | 3300 | 28 | Blue-grey concept glass | CT-101
CT-L09-S-014 | L09 | CURTAIN_PANEL | Glass | CT-L09-S-014 | L09 | South | Curtain wall | GL1 | 1250 | 3300 | 28 | Blue-grey concept glass | CT-101
CT-L09-E-001 | L09 | CURTAIN_PANEL | Glass | CT-L09-E-001 | L09 | East | Curtain wall | GL1 | 1250 | 3300 | 28 | Blue-grey concept glass | CT-102
CT-L09-E-002 | L09 | CURTAIN_PANEL | Glass | CT-L09-E-002 | L09 | East | Curtain wall | GL1 | 1400 | 3300 | 28 | Blue-grey concept glass | CT-102
CT-L09-E-003 | L09 | CURTAIN_PANEL | Glass | CT-L09-E-003 | L09 | East | Curtain wall | GL1 | 1400 | 3300 | 28 | Blue-grey concept glass | CT-102
CT-L09-E-004 | L09 | CURTAIN_PANEL | Glass | CT-L09-E-004 | L09 | East | Curtain wall | GL1 | 1400 | 3300 | 28 | Blue-grey concept glass | CT-102
CT-L09-E-005 | L09 | SHEET | Aluminium | CT-L09-E-005 | L09 | East | Metal rainscreen | AL2 | 1400 | 3300 | 80 | Olive powder coat | CT-102
CT-L09-E-006 | L09 | CURTAIN_PANEL | Glass | CT-L09-E-006 | L09 | East | Curtain wall | GL1 | 1400 | 3300 | 28 | Blue-grey concept glass | CT-102
CT-L09-E-007 | L09 | CURTAIN_PANEL | Glass | CT-L09-E-007 | L09 | East | Curtain wall | GL1 | 1400 | 3300 | 28 | Blue-grey concept glass | CT-102
CT-L09-E-008 | L09 | CURTAIN_PANEL | Glass | CT-L09-E-008 | L09 | East | Curtain wall | GL1 | 1400 | 3300 | 28 | Blue-grey concept glass | CT-102
CT-L09-E-009 | L09 | CURTAIN_PANEL | Glass | CT-L09-E-009 | L09 | East | Curtain wall | GL1 | 1400 | 3300 | 28 | Blue-grey concept glass | CT-102
CT-L09-E-010 | L09 | SHEET | Aluminium | CT-L09-E-010 | L09 | East | Metal rainscreen | AL2 | 1250 | 3300 | 80 | Olive powder coat | CT-102
CT-L09-N-001 | L09 | CURTAIN_PANEL | Glass | CT-L09-N-001 | L09 | North | Curtain wall | GL1 | 1250 | 3300 | 28 | Blue-grey concept glass | CT-103
CT-L09-N-002 | L09 | CURTAIN_PANEL | Glass | CT-L09-N-002 | L09 | North | Curtain wall | GL1 | 1400 | 3300 | 28 | Blue-grey concept glass | CT-103
CT-L09-N-003 | L09 | CURTAIN_PANEL | Glass | CT-L09-N-003 | L09 | North | Curtain wall | GL1 | 1400 | 3300 | 28 | Blue-grey concept glass | CT-103
CT-L09-N-004 | L09 | CURTAIN_PANEL | Glass | CT-L09-N-004 | L09 | North | Curtain wall | GL1 | 1400 | 3300 | 28 | Blue-grey concept glass | CT-103
CT-L09-N-005 | L09 | SHEET | Aluminium | CT-L09-N-005 | L09 | North | Metal rainscreen | AL2 | 1400 | 3300 | 80 | Olive powder coat | CT-103
CT-L09-N-006 | L09 | CURTAIN_PANEL | Glass | CT-L09-N-006 | L09 | North | Curtain wall | GL1 | 1400 | 3300 | 28 | Blue-grey concept glass | CT-103
CT-L09-N-007 | L09 | CURTAIN_PANEL | Glass | CT-L09-N-007 | L09 | North | Curtain wall | GL1 | 1400 | 3300 | 28 | Blue-grey concept glass | CT-103
CT-L09-N-008 | L09 | CURTAIN_PANEL | Glass | CT-L09-N-008 | L09 | North | Curtain wall | GL1 | 1400 | 3300 | 28 | Blue-grey concept glass | CT-103
CT-L09-N-009 | L09 | CURTAIN_PANEL | Glass | CT-L09-N-009 | L09 | North | Curtain wall | GL1 | 1400 | 3300 | 28 | Blue-grey concept glass | CT-103
CT-L09-N-010 | L09 | SHEET | Aluminium | CT-L09-N-010 | L09 | North | Metal rainscreen | AL2 | 1400 | 3300 | 80 | Olive powder coat | CT-103
CT-L09-N-011 | L09 | CURTAIN_PANEL | Glass | CT-L09-N-011 | L09 | North | Curtain wall | GL1 | 1400 | 3300 | 28 | Blue-grey concept glass | CT-103
CT-L09-N-012 | L09 | CURTAIN_PANEL | Glass | CT-L09-N-012 | L09 | North | Curtain wall | GL1 | 1400 | 3300 | 28 | Blue-grey concept glass | CT-103
CT-L09-N-013 | L09 | CURTAIN_PANEL | Glass | CT-L09-N-013 | L09 | North | Curtain wall | GL1 | 1400 | 3300 | 28 | Blue-grey concept glass | CT-103
CT-L09-N-014 | L09 | CURTAIN_PANEL | Glass | CT-L09-N-014 | L09 | North | Curtain wall | GL1 | 1250 | 3300 | 28 | Blue-grey concept glass | CT-103
CT-L09-W-001 | L09 | CURTAIN_PANEL | Glass | CT-L09-W-001 | L09 | West | Curtain wall | GL1 | 1250 | 3300 | 28 | Blue-grey concept glass | CT-104
CT-L09-W-002 | L09 | CURTAIN_PANEL | Glass | CT-L09-W-002 | L09 | West | Curtain wall | GL1 | 1400 | 3300 | 28 | Blue-grey concept glass | CT-104
CT-L09-W-003 | L09 | CURTAIN_PANEL | Glass | CT-L09-W-003 | L09 | West | Curtain wall | GL1 | 1400 | 3300 | 28 | Blue-grey concept glass | CT-104
CT-L09-W-004 | L09 | CURTAIN_PANEL | Glass | CT-L09-W-004 | L09 | West | Curtain wall | GL1 | 1400 | 3300 | 28 | Blue-grey concept glass | CT-104
CT-L09-W-005 | L09 | SHEET | Aluminium | CT-L09-W-005 | L09 | West | Metal rainscreen | AL2 | 1400 | 3300 | 80 | Olive powder coat | CT-104
CT-L09-W-006 | L09 | CURTAIN_PANEL | Glass | CT-L09-W-006 | L09 | West | Curtain wall | GL1 | 1400 | 3300 | 28 | Blue-grey concept glass | CT-104
CT-L09-W-007 | L09 | CURTAIN_PANEL | Glass | CT-L09-W-007 | L09 | West | Curtain wall | GL1 | 1400 | 3300 | 28 | Blue-grey concept glass | CT-104
CT-L09-W-008 | L09 | CURTAIN_PANEL | Glass | CT-L09-W-008 | L09 | West | Curtain wall | GL1 | 1400 | 3300 | 28 | Blue-grey concept glass | CT-104
CT-L09-W-009 | L09 | CURTAIN_PANEL | Glass | CT-L09-W-009 | L09 | West | Curtain wall | GL1 | 1400 | 3300 | 28 | Blue-grey concept glass | CT-104
CT-L09-W-010 | L09 | SHEET | Aluminium | CT-L09-W-010 | L09 | West | Metal rainscreen | AL2 | 1250 | 3300 | 80 | Olive powder coat | CT-104
CT-L10-S-001 | L10 | CURTAIN_PANEL | Glass | CT-L10-S-001 | L10 | South | Curtain wall | GL1 | 1250 | 3300 | 28 | Blue-grey concept glass | CT-101
CT-L10-S-002 | L10 | CURTAIN_PANEL | Glass | CT-L10-S-002 | L10 | South | Curtain wall | GL1 | 1400 | 3300 | 28 | Blue-grey concept glass | CT-101
CT-L10-S-003 | L10 | CURTAIN_PANEL | Glass | CT-L10-S-003 | L10 | South | Curtain wall | GL1 | 1400 | 3300 | 28 | Blue-grey concept glass | CT-101
CT-L10-S-004 | L10 | CURTAIN_PANEL | Glass | CT-L10-S-004 | L10 | South | Curtain wall | GL1 | 1400 | 3300 | 28 | Blue-grey concept glass | CT-101
CT-L10-S-005 | L10 | SHEET | Aluminium | CT-L10-S-005 | L10 | South | Metal rainscreen | AL2 | 1400 | 3300 | 80 | Olive powder coat | CT-101
CT-L10-S-006 | L10 | CURTAIN_PANEL | Glass | CT-L10-S-006 | L10 | South | Curtain wall | GL1 | 1400 | 3300 | 28 | Blue-grey concept glass | CT-101
CT-L10-S-007 | L10 | CURTAIN_PANEL | Glass | CT-L10-S-007 | L10 | South | Curtain wall | GL1 | 1400 | 3300 | 28 | Blue-grey concept glass | CT-101
CT-L10-S-008 | L10 | CURTAIN_PANEL | Glass | CT-L10-S-008 | L10 | South | Curtain wall | GL1 | 1400 | 3300 | 28 | Blue-grey concept glass | CT-101
CT-L10-S-009 | L10 | CURTAIN_PANEL | Glass | CT-L10-S-009 | L10 | South | Curtain wall | GL1 | 1400 | 3300 | 28 | Blue-grey concept glass | CT-101
CT-L10-S-010 | L10 | SHEET | Aluminium | CT-L10-S-010 | L10 | South | Metal rainscreen | AL2 | 1250 | 3300 | 80 | Olive powder coat | CT-101
CT-L10-E-001 | L10 | CURTAIN_PANEL | Glass | CT-L10-E-001 | L10 | East | Curtain wall | GL1 | 1250 | 3300 | 28 | Blue-grey concept glass | CT-102
CT-L10-E-002 | L10 | CURTAIN_PANEL | Glass | CT-L10-E-002 | L10 | East | Curtain wall | GL1 | 1400 | 3300 | 28 | Blue-grey concept glass | CT-102
CT-L10-E-003 | L10 | CURTAIN_PANEL | Glass | CT-L10-E-003 | L10 | East | Curtain wall | GL1 | 1400 | 3300 | 28 | Blue-grey concept glass | CT-102
CT-L10-E-004 | L10 | CURTAIN_PANEL | Glass | CT-L10-E-004 | L10 | East | Curtain wall | GL1 | 1400 | 3300 | 28 | Blue-grey concept glass | CT-102
CT-L10-E-005 | L10 | SHEET | Aluminium | CT-L10-E-005 | L10 | East | Metal rainscreen | AL2 | 1400 | 3300 | 80 | Olive powder coat | CT-102
CT-L10-E-006 | L10 | CURTAIN_PANEL | Glass | CT-L10-E-006 | L10 | East | Curtain wall | GL1 | 1400 | 3300 | 28 | Blue-grey concept glass | CT-102
CT-L10-E-007 | L10 | CURTAIN_PANEL | Glass | CT-L10-E-007 | L10 | East | Curtain wall | GL1 | 1400 | 3300 | 28 | Blue-grey concept glass | CT-102
CT-L10-E-008 | L10 | CURTAIN_PANEL | Glass | CT-L10-E-008 | L10 | East | Curtain wall | GL1 | 1250 | 3300 | 28 | Blue-grey concept glass | CT-102
CT-L10-N-001 | L10 | CURTAIN_PANEL | Glass | CT-L10-N-001 | L10 | North | Curtain wall | GL1 | 1250 | 3300 | 28 | Blue-grey concept glass | CT-103
CT-L10-N-002 | L10 | CURTAIN_PANEL | Glass | CT-L10-N-002 | L10 | North | Curtain wall | GL1 | 1400 | 3300 | 28 | Blue-grey concept glass | CT-103
CT-L10-N-003 | L10 | CURTAIN_PANEL | Glass | CT-L10-N-003 | L10 | North | Curtain wall | GL1 | 1400 | 3300 | 28 | Blue-grey concept glass | CT-103
CT-L10-N-004 | L10 | CURTAIN_PANEL | Glass | CT-L10-N-004 | L10 | North | Curtain wall | GL1 | 1400 | 3300 | 28 | Blue-grey concept glass | CT-103
CT-L10-N-005 | L10 | SHEET | Aluminium | CT-L10-N-005 | L10 | North | Metal rainscreen | AL2 | 1400 | 3300 | 80 | Olive powder coat | CT-103
CT-L10-N-006 | L10 | CURTAIN_PANEL | Glass | CT-L10-N-006 | L10 | North | Curtain wall | GL1 | 1400 | 3300 | 28 | Blue-grey concept glass | CT-103
CT-L10-N-007 | L10 | CURTAIN_PANEL | Glass | CT-L10-N-007 | L10 | North | Curtain wall | GL1 | 1400 | 3300 | 28 | Blue-grey concept glass | CT-103
CT-L10-N-008 | L10 | CURTAIN_PANEL | Glass | CT-L10-N-008 | L10 | North | Curtain wall | GL1 | 1400 | 3300 | 28 | Blue-grey concept glass | CT-103
CT-L10-N-009 | L10 | CURTAIN_PANEL | Glass | CT-L10-N-009 | L10 | North | Curtain wall | GL1 | 1400 | 3300 | 28 | Blue-grey concept glass | CT-103
CT-L10-N-010 | L10 | SHEET | Aluminium | CT-L10-N-010 | L10 | North | Metal rainscreen | AL2 | 1250 | 3300 | 80 | Olive powder coat | CT-103
CT-L10-W-001 | L10 | CURTAIN_PANEL | Glass | CT-L10-W-001 | L10 | West | Curtain wall | GL1 | 1250 | 3300 | 28 | Blue-grey concept glass | CT-104
CT-L10-W-002 | L10 | CURTAIN_PANEL | Glass | CT-L10-W-002 | L10 | West | Curtain wall | GL1 | 1400 | 3300 | 28 | Blue-grey concept glass | CT-104
CT-L10-W-003 | L10 | CURTAIN_PANEL | Glass | CT-L10-W-003 | L10 | West | Curtain wall | GL1 | 1400 | 3300 | 28 | Blue-grey concept glass | CT-104
CT-L10-W-004 | L10 | CURTAIN_PANEL | Glass | CT-L10-W-004 | L10 | West | Curtain wall | GL1 | 1400 | 3300 | 28 | Blue-grey concept glass | CT-104
CT-L10-W-005 | L10 | SHEET | Aluminium | CT-L10-W-005 | L10 | West | Metal rainscreen | AL2 | 1400 | 3300 | 80 | Olive powder coat | CT-104
CT-L10-W-006 | L10 | CURTAIN_PANEL | Glass | CT-L10-W-006 | L10 | West | Curtain wall | GL1 | 1400 | 3300 | 28 | Blue-grey concept glass | CT-104
CT-L10-W-007 | L10 | CURTAIN_PANEL | Glass | CT-L10-W-007 | L10 | West | Curtain wall | GL1 | 1400 | 3300 | 28 | Blue-grey concept glass | CT-104
CT-L10-W-008 | L10 | CURTAIN_PANEL | Glass | CT-L10-W-008 | L10 | West | Curtain wall | GL1 | 1250 | 3300 | 28 | Blue-grey concept glass | CT-104
CT-L11-S-001 | L11 | CURTAIN_PANEL | Glass | CT-L11-S-001 | L11 | South | Curtain wall | GL1 | 1250 | 3300 | 28 | Blue-grey concept glass | CT-101
CT-L11-S-002 | L11 | CURTAIN_PANEL | Glass | CT-L11-S-002 | L11 | South | Curtain wall | GL1 | 1400 | 3300 | 28 | Blue-grey concept glass | CT-101
CT-L11-S-003 | L11 | CURTAIN_PANEL | Glass | CT-L11-S-003 | L11 | South | Curtain wall | GL1 | 1400 | 3300 | 28 | Blue-grey concept glass | CT-101
CT-L11-S-004 | L11 | CURTAIN_PANEL | Glass | CT-L11-S-004 | L11 | South | Curtain wall | GL1 | 1400 | 3300 | 28 | Blue-grey concept glass | CT-101
CT-L11-S-005 | L11 | SHEET | Aluminium | CT-L11-S-005 | L11 | South | Metal rainscreen | AL2 | 1400 | 3300 | 80 | Olive powder coat | CT-101
CT-L11-S-006 | L11 | CURTAIN_PANEL | Glass | CT-L11-S-006 | L11 | South | Curtain wall | GL1 | 1400 | 3300 | 28 | Blue-grey concept glass | CT-101
CT-L11-S-007 | L11 | CURTAIN_PANEL | Glass | CT-L11-S-007 | L11 | South | Curtain wall | GL1 | 1400 | 3300 | 28 | Blue-grey concept glass | CT-101
CT-L11-S-008 | L11 | CURTAIN_PANEL | Glass | CT-L11-S-008 | L11 | South | Curtain wall | GL1 | 1400 | 3300 | 28 | Blue-grey concept glass | CT-101
CT-L11-S-009 | L11 | CURTAIN_PANEL | Glass | CT-L11-S-009 | L11 | South | Curtain wall | GL1 | 1400 | 3300 | 28 | Blue-grey concept glass | CT-101
CT-L11-S-010 | L11 | SHEET | Aluminium | CT-L11-S-010 | L11 | South | Metal rainscreen | AL2 | 1250 | 3300 | 80 | Olive powder coat | CT-101
CT-L11-E-001 | L11 | CURTAIN_PANEL | Glass | CT-L11-E-001 | L11 | East | Curtain wall | GL1 | 1250 | 3300 | 28 | Blue-grey concept glass | CT-102
CT-L11-E-002 | L11 | CURTAIN_PANEL | Glass | CT-L11-E-002 | L11 | East | Curtain wall | GL1 | 1400 | 3300 | 28 | Blue-grey concept glass | CT-102
CT-L11-E-003 | L11 | CURTAIN_PANEL | Glass | CT-L11-E-003 | L11 | East | Curtain wall | GL1 | 1400 | 3300 | 28 | Blue-grey concept glass | CT-102
CT-L11-E-004 | L11 | CURTAIN_PANEL | Glass | CT-L11-E-004 | L11 | East | Curtain wall | GL1 | 1400 | 3300 | 28 | Blue-grey concept glass | CT-102
CT-L11-E-005 | L11 | SHEET | Aluminium | CT-L11-E-005 | L11 | East | Metal rainscreen | AL2 | 1400 | 3300 | 80 | Olive powder coat | CT-102
CT-L11-E-006 | L11 | CURTAIN_PANEL | Glass | CT-L11-E-006 | L11 | East | Curtain wall | GL1 | 1400 | 3300 | 28 | Blue-grey concept glass | CT-102
CT-L11-E-007 | L11 | CURTAIN_PANEL | Glass | CT-L11-E-007 | L11 | East | Curtain wall | GL1 | 1400 | 3300 | 28 | Blue-grey concept glass | CT-102
CT-L11-E-008 | L11 | CURTAIN_PANEL | Glass | CT-L11-E-008 | L11 | East | Curtain wall | GL1 | 1250 | 3300 | 28 | Blue-grey concept glass | CT-102
CT-L11-N-001 | L11 | CURTAIN_PANEL | Glass | CT-L11-N-001 | L11 | North | Curtain wall | GL1 | 1250 | 3300 | 28 | Blue-grey concept glass | CT-103
CT-L11-N-002 | L11 | CURTAIN_PANEL | Glass | CT-L11-N-002 | L11 | North | Curtain wall | GL1 | 1400 | 3300 | 28 | Blue-grey concept glass | CT-103
CT-L11-N-003 | L11 | CURTAIN_PANEL | Glass | CT-L11-N-003 | L11 | North | Curtain wall | GL1 | 1400 | 3300 | 28 | Blue-grey concept glass | CT-103
CT-L11-N-004 | L11 | CURTAIN_PANEL | Glass | CT-L11-N-004 | L11 | North | Curtain wall | GL1 | 1400 | 3300 | 28 | Blue-grey concept glass | CT-103
CT-L11-N-005 | L11 | SHEET | Aluminium | CT-L11-N-005 | L11 | North | Metal rainscreen | AL2 | 1400 | 3300 | 80 | Olive powder coat | CT-103
CT-L11-N-006 | L11 | CURTAIN_PANEL | Glass | CT-L11-N-006 | L11 | North | Curtain wall | GL1 | 1400 | 3300 | 28 | Blue-grey concept glass | CT-103
CT-L11-N-007 | L11 | CURTAIN_PANEL | Glass | CT-L11-N-007 | L11 | North | Curtain wall | GL1 | 1400 | 3300 | 28 | Blue-grey concept glass | CT-103
CT-L11-N-008 | L11 | CURTAIN_PANEL | Glass | CT-L11-N-008 | L11 | North | Curtain wall | GL1 | 1400 | 3300 | 28 | Blue-grey concept glass | CT-103
CT-L11-N-009 | L11 | CURTAIN_PANEL | Glass | CT-L11-N-009 | L11 | North | Curtain wall | GL1 | 1400 | 3300 | 28 | Blue-grey concept glass | CT-103
CT-L11-N-010 | L11 | SHEET | Aluminium | CT-L11-N-010 | L11 | North | Metal rainscreen | AL2 | 1250 | 3300 | 80 | Olive powder coat | CT-103
CT-L11-W-001 | L11 | CURTAIN_PANEL | Glass | CT-L11-W-001 | L11 | West | Curtain wall | GL1 | 1250 | 3300 | 28 | Blue-grey concept glass | CT-104
CT-L11-W-002 | L11 | CURTAIN_PANEL | Glass | CT-L11-W-002 | L11 | West | Curtain wall | GL1 | 1400 | 3300 | 28 | Blue-grey concept glass | CT-104
CT-L11-W-003 | L11 | CURTAIN_PANEL | Glass | CT-L11-W-003 | L11 | West | Curtain wall | GL1 | 1400 | 3300 | 28 | Blue-grey concept glass | CT-104
CT-L11-W-004 | L11 | CURTAIN_PANEL | Glass | CT-L11-W-004 | L11 | West | Curtain wall | GL1 | 1400 | 3300 | 28 | Blue-grey concept glass | CT-104
CT-L11-W-005 | L11 | SHEET | Aluminium | CT-L11-W-005 | L11 | West | Metal rainscreen | AL2 | 1400 | 3300 | 80 | Olive powder coat | CT-104
CT-L11-W-006 | L11 | CURTAIN_PANEL | Glass | CT-L11-W-006 | L11 | West | Curtain wall | GL1 | 1400 | 3300 | 28 | Blue-grey concept glass | CT-104
CT-L11-W-007 | L11 | CURTAIN_PANEL | Glass | CT-L11-W-007 | L11 | West | Curtain wall | GL1 | 1400 | 3300 | 28 | Blue-grey concept glass | CT-104
CT-L11-W-008 | L11 | CURTAIN_PANEL | Glass | CT-L11-W-008 | L11 | West | Curtain wall | GL1 | 1250 | 3300 | 28 | Blue-grey concept glass | CT-104
CT-L12-S-001 | L12 | CURTAIN_PANEL | Glass | CT-L12-S-001 | L12 | South | Curtain wall | GL1 | 1250 | 3300 | 28 | Blue-grey concept glass | CT-101
CT-L12-S-002 | L12 | CURTAIN_PANEL | Glass | CT-L12-S-002 | L12 | South | Curtain wall | GL1 | 1400 | 3300 | 28 | Blue-grey concept glass | CT-101
CT-L12-S-003 | L12 | CURTAIN_PANEL | Glass | CT-L12-S-003 | L12 | South | Curtain wall | GL1 | 1400 | 3300 | 28 | Blue-grey concept glass | CT-101
CT-L12-S-004 | L12 | CURTAIN_PANEL | Glass | CT-L12-S-004 | L12 | South | Curtain wall | GL1 | 1400 | 3300 | 28 | Blue-grey concept glass | CT-101
CT-L12-S-005 | L12 | SHEET | Aluminium | CT-L12-S-005 | L12 | South | Metal rainscreen | AL2 | 1400 | 3300 | 80 | Olive powder coat | CT-101
CT-L12-S-006 | L12 | CURTAIN_PANEL | Glass | CT-L12-S-006 | L12 | South | Curtain wall | GL1 | 1400 | 3300 | 28 | Blue-grey concept glass | CT-101
CT-L12-S-007 | L12 | CURTAIN_PANEL | Glass | CT-L12-S-007 | L12 | South | Curtain wall | GL1 | 1400 | 3300 | 28 | Blue-grey concept glass | CT-101
CT-L12-S-008 | L12 | CURTAIN_PANEL | Glass | CT-L12-S-008 | L12 | South | Curtain wall | GL1 | 1400 | 3300 | 28 | Blue-grey concept glass | CT-101
CT-L12-S-009 | L12 | CURTAIN_PANEL | Glass | CT-L12-S-009 | L12 | South | Curtain wall | GL1 | 1400 | 3300 | 28 | Blue-grey concept glass | CT-101
CT-L12-S-010 | L12 | SHEET | Aluminium | CT-L12-S-010 | L12 | South | Metal rainscreen | AL2 | 1250 | 3300 | 80 | Olive powder coat | CT-101
CT-L12-E-001 | L12 | CURTAIN_PANEL | Glass | CT-L12-E-001 | L12 | East | Curtain wall | GL1 | 1250 | 3300 | 28 | Blue-grey concept glass | CT-102
CT-L12-E-002 | L12 | CURTAIN_PANEL | Glass | CT-L12-E-002 | L12 | East | Curtain wall | GL1 | 1400 | 3300 | 28 | Blue-grey concept glass | CT-102
CT-L12-E-003 | L12 | CURTAIN_PANEL | Glass | CT-L12-E-003 | L12 | East | Curtain wall | GL1 | 1400 | 3300 | 28 | Blue-grey concept glass | CT-102
CT-L12-E-004 | L12 | CURTAIN_PANEL | Glass | CT-L12-E-004 | L12 | East | Curtain wall | GL1 | 1400 | 3300 | 28 | Blue-grey concept glass | CT-102
CT-L12-E-005 | L12 | SHEET | Aluminium | CT-L12-E-005 | L12 | East | Metal rainscreen | AL2 | 1400 | 3300 | 80 | Olive powder coat | CT-102
CT-L12-E-006 | L12 | CURTAIN_PANEL | Glass | CT-L12-E-006 | L12 | East | Curtain wall | GL1 | 1400 | 3300 | 28 | Blue-grey concept glass | CT-102
CT-L12-E-007 | L12 | CURTAIN_PANEL | Glass | CT-L12-E-007 | L12 | East | Curtain wall | GL1 | 1400 | 3300 | 28 | Blue-grey concept glass | CT-102
CT-L12-E-008 | L12 | CURTAIN_PANEL | Glass | CT-L12-E-008 | L12 | East | Curtain wall | GL1 | 1250 | 3300 | 28 | Blue-grey concept glass | CT-102
CT-L12-N-001 | L12 | CURTAIN_PANEL | Glass | CT-L12-N-001 | L12 | North | Curtain wall | GL1 | 1250 | 3300 | 28 | Blue-grey concept glass | CT-103
CT-L12-N-002 | L12 | CURTAIN_PANEL | Glass | CT-L12-N-002 | L12 | North | Curtain wall | GL1 | 1400 | 3300 | 28 | Blue-grey concept glass | CT-103
CT-L12-N-003 | L12 | CURTAIN_PANEL | Glass | CT-L12-N-003 | L12 | North | Curtain wall | GL1 | 1400 | 3300 | 28 | Blue-grey concept glass | CT-103
CT-L12-N-004 | L12 | CURTAIN_PANEL | Glass | CT-L12-N-004 | L12 | North | Curtain wall | GL1 | 1400 | 3300 | 28 | Blue-grey concept glass | CT-103
CT-L12-N-005 | L12 | SHEET | Aluminium | CT-L12-N-005 | L12 | North | Metal rainscreen | AL2 | 1400 | 3300 | 80 | Olive powder coat | CT-103
CT-L12-N-006 | L12 | CURTAIN_PANEL | Glass | CT-L12-N-006 | L12 | North | Curtain wall | GL1 | 1400 | 3300 | 28 | Blue-grey concept glass | CT-103
CT-L12-N-007 | L12 | CURTAIN_PANEL | Glass | CT-L12-N-007 | L12 | North | Curtain wall | GL1 | 1400 | 3300 | 28 | Blue-grey concept glass | CT-103
CT-L12-N-008 | L12 | CURTAIN_PANEL | Glass | CT-L12-N-008 | L12 | North | Curtain wall | GL1 | 1400 | 3300 | 28 | Blue-grey concept glass | CT-103
CT-L12-N-009 | L12 | CURTAIN_PANEL | Glass | CT-L12-N-009 | L12 | North | Curtain wall | GL1 | 1400 | 3300 | 28 | Blue-grey concept glass | CT-103
CT-L12-N-010 | L12 | SHEET | Aluminium | CT-L12-N-010 | L12 | North | Metal rainscreen | AL2 | 1250 | 3300 | 80 | Olive powder coat | CT-103
CT-L12-W-001 | L12 | CURTAIN_PANEL | Glass | CT-L12-W-001 | L12 | West | Curtain wall | GL1 | 1250 | 3300 | 28 | Blue-grey concept glass | CT-104
CT-L12-W-002 | L12 | CURTAIN_PANEL | Glass | CT-L12-W-002 | L12 | West | Curtain wall | GL1 | 1400 | 3300 | 28 | Blue-grey concept glass | CT-104
CT-L12-W-003 | L12 | CURTAIN_PANEL | Glass | CT-L12-W-003 | L12 | West | Curtain wall | GL1 | 1400 | 3300 | 28 | Blue-grey concept glass | CT-104
CT-L12-W-004 | L12 | CURTAIN_PANEL | Glass | CT-L12-W-004 | L12 | West | Curtain wall | GL1 | 1400 | 3300 | 28 | Blue-grey concept glass | CT-104
CT-L12-W-005 | L12 | SHEET | Aluminium | CT-L12-W-005 | L12 | West | Metal rainscreen | AL2 | 1400 | 3300 | 80 | Olive powder coat | CT-104
CT-L12-W-006 | L12 | CURTAIN_PANEL | Glass | CT-L12-W-006 | L12 | West | Curtain wall | GL1 | 1400 | 3300 | 28 | Blue-grey concept glass | CT-104
CT-L12-W-007 | L12 | CURTAIN_PANEL | Glass | CT-L12-W-007 | L12 | West | Curtain wall | GL1 | 1400 | 3300 | 28 | Blue-grey concept glass | CT-104
CT-L12-W-008 | L12 | CURTAIN_PANEL | Glass | CT-L12-W-008 | L12 | West | Curtain wall | GL1 | 1250 | 3300 | 28 | Blue-grey concept glass | CT-104

# IfcSlab (13)
Material: Concrete; Group: Structure
ConX_Element - SyntheticData: yes; System: Structure
Name | In | PredefinedType | ElementID | Floor
CT-SLAB-01 | L01 | FLOOR | CT-SLAB-01 | L01
CT-SLAB-02 | L02 | FLOOR | CT-SLAB-02 | L02
CT-SLAB-03 | L03 | FLOOR | CT-SLAB-03 | L03
CT-SLAB-04 | L04 | FLOOR | CT-SLAB-04 | L04
CT-SLAB-05 | L05 | FLOOR | CT-SLAB-05 | L05
CT-SLAB-06 | L06 | FLOOR | CT-SLAB-06 | L06
CT-SLAB-07 | L07 | FLOOR | CT-SLAB-07 | L07
CT-SLAB-08 | L08 | FLOOR | CT-SLAB-08 | L08
CT-SLAB-09 | L09 | FLOOR | CT-SLAB-09 | L09
CT-SLAB-10 | L10 | FLOOR | CT-SLAB-10 | L10
CT-SLAB-11 | L11 | FLOOR | CT-SLAB-11 | L11
CT-SLAB-12 | L12 | FLOOR | CT-SLAB-12 | L12
CT-ROOF | L12 | ROOF | CT-ROOF | L12
